# Generated by FakeRAM 2.0
VERSION 5.7 ;
BUSBITCHARS "[]" ;
PROPERTYDEFINITIONS
  MACRO width INTEGER ;
  MACRO depth INTEGER ;
  MACRO banks INTEGER ;
END PROPERTYDEFINITIONS
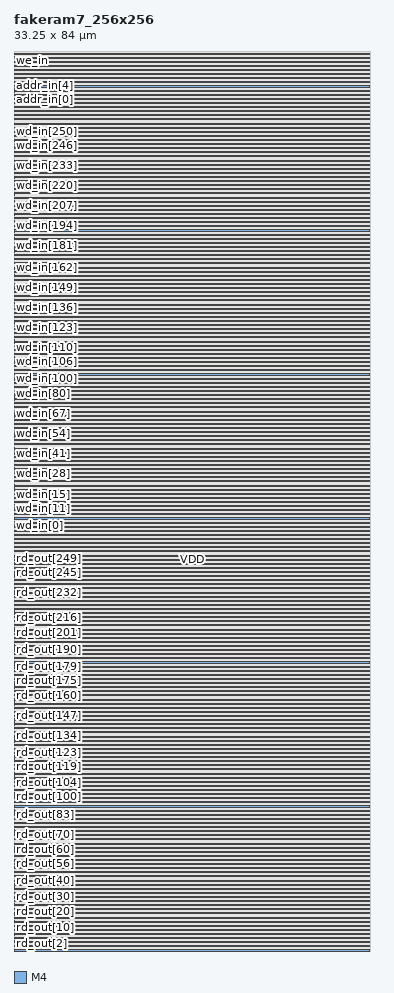
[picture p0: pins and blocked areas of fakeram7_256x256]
MACRO fakeram7_256x256
  PROPERTY width 256 ;
  PROPERTY depth 256 ;
  PROPERTY banks 1 ;
  FOREIGN fakeram7_256x256 0 0 ;
  SYMMETRY X Y R90 ;
  SIZE 33.250 BY 84.000 ;
  CLASS BLOCK ;
  PIN rd_out[0]
    DIRECTION OUTPUT ;
    USE SIGNAL ;
    SHAPE ABUTMENT ;
    PORT
      LAYER M4 ;
      RECT 0.000 0.048 0.024 0.072 ;
    END
  END rd_out[0]
  PIN rd_out[1]
    DIRECTION OUTPUT ;
    USE SIGNAL ;
    SHAPE ABUTMENT ;
    PORT
      LAYER M4 ;
      RECT 0.000 0.192 0.024 0.216 ;
    END
  END rd_out[1]
  PIN rd_out[2]
    DIRECTION OUTPUT ;
    USE SIGNAL ;
    SHAPE ABUTMENT ;
    PORT
      LAYER M4 ;
      RECT 0.000 0.336 0.024 0.360 ;
    END
  END rd_out[2]
  PIN rd_out[3]
    DIRECTION OUTPUT ;
    USE SIGNAL ;
    SHAPE ABUTMENT ;
    PORT
      LAYER M4 ;
      RECT 0.000 0.480 0.024 0.504 ;
    END
  END rd_out[3]
  PIN rd_out[4]
    DIRECTION OUTPUT ;
    USE SIGNAL ;
    SHAPE ABUTMENT ;
    PORT
      LAYER M4 ;
      RECT 0.000 0.624 0.024 0.648 ;
    END
  END rd_out[4]
  PIN rd_out[5]
    DIRECTION OUTPUT ;
    USE SIGNAL ;
    SHAPE ABUTMENT ;
    PORT
      LAYER M4 ;
      RECT 0.000 0.768 0.024 0.792 ;
    END
  END rd_out[5]
  PIN rd_out[6]
    DIRECTION OUTPUT ;
    USE SIGNAL ;
    SHAPE ABUTMENT ;
    PORT
      LAYER M4 ;
      RECT 0.000 0.912 0.024 0.936 ;
    END
  END rd_out[6]
  PIN rd_out[7]
    DIRECTION OUTPUT ;
    USE SIGNAL ;
    SHAPE ABUTMENT ;
    PORT
      LAYER M4 ;
      RECT 0.000 1.056 0.024 1.080 ;
    END
  END rd_out[7]
  PIN rd_out[8]
    DIRECTION OUTPUT ;
    USE SIGNAL ;
    SHAPE ABUTMENT ;
    PORT
      LAYER M4 ;
      RECT 0.000 1.200 0.024 1.224 ;
    END
  END rd_out[8]
  PIN rd_out[9]
    DIRECTION OUTPUT ;
    USE SIGNAL ;
    SHAPE ABUTMENT ;
    PORT
      LAYER M4 ;
      RECT 0.000 1.344 0.024 1.368 ;
    END
  END rd_out[9]
  PIN rd_out[10]
    DIRECTION OUTPUT ;
    USE SIGNAL ;
    SHAPE ABUTMENT ;
    PORT
      LAYER M4 ;
      RECT 0.000 1.488 0.024 1.512 ;
    END
  END rd_out[10]
  PIN rd_out[11]
    DIRECTION OUTPUT ;
    USE SIGNAL ;
    SHAPE ABUTMENT ;
    PORT
      LAYER M4 ;
      RECT 0.000 1.632 0.024 1.656 ;
    END
  END rd_out[11]
  PIN rd_out[12]
    DIRECTION OUTPUT ;
    USE SIGNAL ;
    SHAPE ABUTMENT ;
    PORT
      LAYER M4 ;
      RECT 0.000 1.776 0.024 1.800 ;
    END
  END rd_out[12]
  PIN rd_out[13]
    DIRECTION OUTPUT ;
    USE SIGNAL ;
    SHAPE ABUTMENT ;
    PORT
      LAYER M4 ;
      RECT 0.000 1.920 0.024 1.944 ;
    END
  END rd_out[13]
  PIN rd_out[14]
    DIRECTION OUTPUT ;
    USE SIGNAL ;
    SHAPE ABUTMENT ;
    PORT
      LAYER M4 ;
      RECT 0.000 2.064 0.024 2.088 ;
    END
  END rd_out[14]
  PIN rd_out[15]
    DIRECTION OUTPUT ;
    USE SIGNAL ;
    SHAPE ABUTMENT ;
    PORT
      LAYER M4 ;
      RECT 0.000 2.208 0.024 2.232 ;
    END
  END rd_out[15]
  PIN rd_out[16]
    DIRECTION OUTPUT ;
    USE SIGNAL ;
    SHAPE ABUTMENT ;
    PORT
      LAYER M4 ;
      RECT 0.000 2.352 0.024 2.376 ;
    END
  END rd_out[16]
  PIN rd_out[17]
    DIRECTION OUTPUT ;
    USE SIGNAL ;
    SHAPE ABUTMENT ;
    PORT
      LAYER M4 ;
      RECT 0.000 2.496 0.024 2.520 ;
    END
  END rd_out[17]
  PIN rd_out[18]
    DIRECTION OUTPUT ;
    USE SIGNAL ;
    SHAPE ABUTMENT ;
    PORT
      LAYER M4 ;
      RECT 0.000 2.640 0.024 2.664 ;
    END
  END rd_out[18]
  PIN rd_out[19]
    DIRECTION OUTPUT ;
    USE SIGNAL ;
    SHAPE ABUTMENT ;
    PORT
      LAYER M4 ;
      RECT 0.000 2.784 0.024 2.808 ;
    END
  END rd_out[19]
  PIN rd_out[20]
    DIRECTION OUTPUT ;
    USE SIGNAL ;
    SHAPE ABUTMENT ;
    PORT
      LAYER M4 ;
      RECT 0.000 2.928 0.024 2.952 ;
    END
  END rd_out[20]
  PIN rd_out[21]
    DIRECTION OUTPUT ;
    USE SIGNAL ;
    SHAPE ABUTMENT ;
    PORT
      LAYER M4 ;
      RECT 0.000 3.072 0.024 3.096 ;
    END
  END rd_out[21]
  PIN rd_out[22]
    DIRECTION OUTPUT ;
    USE SIGNAL ;
    SHAPE ABUTMENT ;
    PORT
      LAYER M4 ;
      RECT 0.000 3.216 0.024 3.240 ;
    END
  END rd_out[22]
  PIN rd_out[23]
    DIRECTION OUTPUT ;
    USE SIGNAL ;
    SHAPE ABUTMENT ;
    PORT
      LAYER M4 ;
      RECT 0.000 3.360 0.024 3.384 ;
    END
  END rd_out[23]
  PIN rd_out[24]
    DIRECTION OUTPUT ;
    USE SIGNAL ;
    SHAPE ABUTMENT ;
    PORT
      LAYER M4 ;
      RECT 0.000 3.504 0.024 3.528 ;
    END
  END rd_out[24]
  PIN rd_out[25]
    DIRECTION OUTPUT ;
    USE SIGNAL ;
    SHAPE ABUTMENT ;
    PORT
      LAYER M4 ;
      RECT 0.000 3.648 0.024 3.672 ;
    END
  END rd_out[25]
  PIN rd_out[26]
    DIRECTION OUTPUT ;
    USE SIGNAL ;
    SHAPE ABUTMENT ;
    PORT
      LAYER M4 ;
      RECT 0.000 3.792 0.024 3.816 ;
    END
  END rd_out[26]
  PIN rd_out[27]
    DIRECTION OUTPUT ;
    USE SIGNAL ;
    SHAPE ABUTMENT ;
    PORT
      LAYER M4 ;
      RECT 0.000 3.936 0.024 3.960 ;
    END
  END rd_out[27]
  PIN rd_out[28]
    DIRECTION OUTPUT ;
    USE SIGNAL ;
    SHAPE ABUTMENT ;
    PORT
      LAYER M4 ;
      RECT 0.000 4.080 0.024 4.104 ;
    END
  END rd_out[28]
  PIN rd_out[29]
    DIRECTION OUTPUT ;
    USE SIGNAL ;
    SHAPE ABUTMENT ;
    PORT
      LAYER M4 ;
      RECT 0.000 4.224 0.024 4.248 ;
    END
  END rd_out[29]
  PIN rd_out[30]
    DIRECTION OUTPUT ;
    USE SIGNAL ;
    SHAPE ABUTMENT ;
    PORT
      LAYER M4 ;
      RECT 0.000 4.368 0.024 4.392 ;
    END
  END rd_out[30]
  PIN rd_out[31]
    DIRECTION OUTPUT ;
    USE SIGNAL ;
    SHAPE ABUTMENT ;
    PORT
      LAYER M4 ;
      RECT 0.000 4.512 0.024 4.536 ;
    END
  END rd_out[31]
  PIN rd_out[32]
    DIRECTION OUTPUT ;
    USE SIGNAL ;
    SHAPE ABUTMENT ;
    PORT
      LAYER M4 ;
      RECT 0.000 4.656 0.024 4.680 ;
    END
  END rd_out[32]
  PIN rd_out[33]
    DIRECTION OUTPUT ;
    USE SIGNAL ;
    SHAPE ABUTMENT ;
    PORT
      LAYER M4 ;
      RECT 0.000 4.800 0.024 4.824 ;
    END
  END rd_out[33]
  PIN rd_out[34]
    DIRECTION OUTPUT ;
    USE SIGNAL ;
    SHAPE ABUTMENT ;
    PORT
      LAYER M4 ;
      RECT 0.000 4.944 0.024 4.968 ;
    END
  END rd_out[34]
  PIN rd_out[35]
    DIRECTION OUTPUT ;
    USE SIGNAL ;
    SHAPE ABUTMENT ;
    PORT
      LAYER M4 ;
      RECT 0.000 5.088 0.024 5.112 ;
    END
  END rd_out[35]
  PIN rd_out[36]
    DIRECTION OUTPUT ;
    USE SIGNAL ;
    SHAPE ABUTMENT ;
    PORT
      LAYER M4 ;
      RECT 0.000 5.232 0.024 5.256 ;
    END
  END rd_out[36]
  PIN rd_out[37]
    DIRECTION OUTPUT ;
    USE SIGNAL ;
    SHAPE ABUTMENT ;
    PORT
      LAYER M4 ;
      RECT 0.000 5.376 0.024 5.400 ;
    END
  END rd_out[37]
  PIN rd_out[38]
    DIRECTION OUTPUT ;
    USE SIGNAL ;
    SHAPE ABUTMENT ;
    PORT
      LAYER M4 ;
      RECT 0.000 5.520 0.024 5.544 ;
    END
  END rd_out[38]
  PIN rd_out[39]
    DIRECTION OUTPUT ;
    USE SIGNAL ;
    SHAPE ABUTMENT ;
    PORT
      LAYER M4 ;
      RECT 0.000 5.664 0.024 5.688 ;
    END
  END rd_out[39]
  PIN rd_out[40]
    DIRECTION OUTPUT ;
    USE SIGNAL ;
    SHAPE ABUTMENT ;
    PORT
      LAYER M4 ;
      RECT 0.000 5.808 0.024 5.832 ;
    END
  END rd_out[40]
  PIN rd_out[41]
    DIRECTION OUTPUT ;
    USE SIGNAL ;
    SHAPE ABUTMENT ;
    PORT
      LAYER M4 ;
      RECT 0.000 5.952 0.024 5.976 ;
    END
  END rd_out[41]
  PIN rd_out[42]
    DIRECTION OUTPUT ;
    USE SIGNAL ;
    SHAPE ABUTMENT ;
    PORT
      LAYER M4 ;
      RECT 0.000 6.096 0.024 6.120 ;
    END
  END rd_out[42]
  PIN rd_out[43]
    DIRECTION OUTPUT ;
    USE SIGNAL ;
    SHAPE ABUTMENT ;
    PORT
      LAYER M4 ;
      RECT 0.000 6.240 0.024 6.264 ;
    END
  END rd_out[43]
  PIN rd_out[44]
    DIRECTION OUTPUT ;
    USE SIGNAL ;
    SHAPE ABUTMENT ;
    PORT
      LAYER M4 ;
      RECT 0.000 6.384 0.024 6.408 ;
    END
  END rd_out[44]
  PIN rd_out[45]
    DIRECTION OUTPUT ;
    USE SIGNAL ;
    SHAPE ABUTMENT ;
    PORT
      LAYER M4 ;
      RECT 0.000 6.528 0.024 6.552 ;
    END
  END rd_out[45]
  PIN rd_out[46]
    DIRECTION OUTPUT ;
    USE SIGNAL ;
    SHAPE ABUTMENT ;
    PORT
      LAYER M4 ;
      RECT 0.000 6.672 0.024 6.696 ;
    END
  END rd_out[46]
  PIN rd_out[47]
    DIRECTION OUTPUT ;
    USE SIGNAL ;
    SHAPE ABUTMENT ;
    PORT
      LAYER M4 ;
      RECT 0.000 6.816 0.024 6.840 ;
    END
  END rd_out[47]
  PIN rd_out[48]
    DIRECTION OUTPUT ;
    USE SIGNAL ;
    SHAPE ABUTMENT ;
    PORT
      LAYER M4 ;
      RECT 0.000 6.960 0.024 6.984 ;
    END
  END rd_out[48]
  PIN rd_out[49]
    DIRECTION OUTPUT ;
    USE SIGNAL ;
    SHAPE ABUTMENT ;
    PORT
      LAYER M4 ;
      RECT 0.000 7.104 0.024 7.128 ;
    END
  END rd_out[49]
  PIN rd_out[50]
    DIRECTION OUTPUT ;
    USE SIGNAL ;
    SHAPE ABUTMENT ;
    PORT
      LAYER M4 ;
      RECT 0.000 7.248 0.024 7.272 ;
    END
  END rd_out[50]
  PIN rd_out[51]
    DIRECTION OUTPUT ;
    USE SIGNAL ;
    SHAPE ABUTMENT ;
    PORT
      LAYER M4 ;
      RECT 0.000 7.392 0.024 7.416 ;
    END
  END rd_out[51]
  PIN rd_out[52]
    DIRECTION OUTPUT ;
    USE SIGNAL ;
    SHAPE ABUTMENT ;
    PORT
      LAYER M4 ;
      RECT 0.000 7.536 0.024 7.560 ;
    END
  END rd_out[52]
  PIN rd_out[53]
    DIRECTION OUTPUT ;
    USE SIGNAL ;
    SHAPE ABUTMENT ;
    PORT
      LAYER M4 ;
      RECT 0.000 7.680 0.024 7.704 ;
    END
  END rd_out[53]
  PIN rd_out[54]
    DIRECTION OUTPUT ;
    USE SIGNAL ;
    SHAPE ABUTMENT ;
    PORT
      LAYER M4 ;
      RECT 0.000 7.824 0.024 7.848 ;
    END
  END rd_out[54]
  PIN rd_out[55]
    DIRECTION OUTPUT ;
    USE SIGNAL ;
    SHAPE ABUTMENT ;
    PORT
      LAYER M4 ;
      RECT 0.000 7.968 0.024 7.992 ;
    END
  END rd_out[55]
  PIN rd_out[56]
    DIRECTION OUTPUT ;
    USE SIGNAL ;
    SHAPE ABUTMENT ;
    PORT
      LAYER M4 ;
      RECT 0.000 8.112 0.024 8.136 ;
    END
  END rd_out[56]
  PIN rd_out[57]
    DIRECTION OUTPUT ;
    USE SIGNAL ;
    SHAPE ABUTMENT ;
    PORT
      LAYER M4 ;
      RECT 0.000 8.256 0.024 8.280 ;
    END
  END rd_out[57]
  PIN rd_out[58]
    DIRECTION OUTPUT ;
    USE SIGNAL ;
    SHAPE ABUTMENT ;
    PORT
      LAYER M4 ;
      RECT 0.000 8.400 0.024 8.424 ;
    END
  END rd_out[58]
  PIN rd_out[59]
    DIRECTION OUTPUT ;
    USE SIGNAL ;
    SHAPE ABUTMENT ;
    PORT
      LAYER M4 ;
      RECT 0.000 8.544 0.024 8.568 ;
    END
  END rd_out[59]
  PIN rd_out[60]
    DIRECTION OUTPUT ;
    USE SIGNAL ;
    SHAPE ABUTMENT ;
    PORT
      LAYER M4 ;
      RECT 0.000 8.688 0.024 8.712 ;
    END
  END rd_out[60]
  PIN rd_out[61]
    DIRECTION OUTPUT ;
    USE SIGNAL ;
    SHAPE ABUTMENT ;
    PORT
      LAYER M4 ;
      RECT 0.000 8.832 0.024 8.856 ;
    END
  END rd_out[61]
  PIN rd_out[62]
    DIRECTION OUTPUT ;
    USE SIGNAL ;
    SHAPE ABUTMENT ;
    PORT
      LAYER M4 ;
      RECT 0.000 8.976 0.024 9.000 ;
    END
  END rd_out[62]
  PIN rd_out[63]
    DIRECTION OUTPUT ;
    USE SIGNAL ;
    SHAPE ABUTMENT ;
    PORT
      LAYER M4 ;
      RECT 0.000 9.120 0.024 9.144 ;
    END
  END rd_out[63]
  PIN rd_out[64]
    DIRECTION OUTPUT ;
    USE SIGNAL ;
    SHAPE ABUTMENT ;
    PORT
      LAYER M4 ;
      RECT 0.000 9.264 0.024 9.288 ;
    END
  END rd_out[64]
  PIN rd_out[65]
    DIRECTION OUTPUT ;
    USE SIGNAL ;
    SHAPE ABUTMENT ;
    PORT
      LAYER M4 ;
      RECT 0.000 9.408 0.024 9.432 ;
    END
  END rd_out[65]
  PIN rd_out[66]
    DIRECTION OUTPUT ;
    USE SIGNAL ;
    SHAPE ABUTMENT ;
    PORT
      LAYER M4 ;
      RECT 0.000 9.552 0.024 9.576 ;
    END
  END rd_out[66]
  PIN rd_out[67]
    DIRECTION OUTPUT ;
    USE SIGNAL ;
    SHAPE ABUTMENT ;
    PORT
      LAYER M4 ;
      RECT 0.000 9.696 0.024 9.720 ;
    END
  END rd_out[67]
  PIN rd_out[68]
    DIRECTION OUTPUT ;
    USE SIGNAL ;
    SHAPE ABUTMENT ;
    PORT
      LAYER M4 ;
      RECT 0.000 9.840 0.024 9.864 ;
    END
  END rd_out[68]
  PIN rd_out[69]
    DIRECTION OUTPUT ;
    USE SIGNAL ;
    SHAPE ABUTMENT ;
    PORT
      LAYER M4 ;
      RECT 0.000 9.984 0.024 10.008 ;
    END
  END rd_out[69]
  PIN rd_out[70]
    DIRECTION OUTPUT ;
    USE SIGNAL ;
    SHAPE ABUTMENT ;
    PORT
      LAYER M4 ;
      RECT 0.000 10.128 0.024 10.152 ;
    END
  END rd_out[70]
  PIN rd_out[71]
    DIRECTION OUTPUT ;
    USE SIGNAL ;
    SHAPE ABUTMENT ;
    PORT
      LAYER M4 ;
      RECT 0.000 10.272 0.024 10.296 ;
    END
  END rd_out[71]
  PIN rd_out[72]
    DIRECTION OUTPUT ;
    USE SIGNAL ;
    SHAPE ABUTMENT ;
    PORT
      LAYER M4 ;
      RECT 0.000 10.416 0.024 10.440 ;
    END
  END rd_out[72]
  PIN rd_out[73]
    DIRECTION OUTPUT ;
    USE SIGNAL ;
    SHAPE ABUTMENT ;
    PORT
      LAYER M4 ;
      RECT 0.000 10.560 0.024 10.584 ;
    END
  END rd_out[73]
  PIN rd_out[74]
    DIRECTION OUTPUT ;
    USE SIGNAL ;
    SHAPE ABUTMENT ;
    PORT
      LAYER M4 ;
      RECT 0.000 10.704 0.024 10.728 ;
    END
  END rd_out[74]
  PIN rd_out[75]
    DIRECTION OUTPUT ;
    USE SIGNAL ;
    SHAPE ABUTMENT ;
    PORT
      LAYER M4 ;
      RECT 0.000 10.848 0.024 10.872 ;
    END
  END rd_out[75]
  PIN rd_out[76]
    DIRECTION OUTPUT ;
    USE SIGNAL ;
    SHAPE ABUTMENT ;
    PORT
      LAYER M4 ;
      RECT 0.000 10.992 0.024 11.016 ;
    END
  END rd_out[76]
  PIN rd_out[77]
    DIRECTION OUTPUT ;
    USE SIGNAL ;
    SHAPE ABUTMENT ;
    PORT
      LAYER M4 ;
      RECT 0.000 11.136 0.024 11.160 ;
    END
  END rd_out[77]
  PIN rd_out[78]
    DIRECTION OUTPUT ;
    USE SIGNAL ;
    SHAPE ABUTMENT ;
    PORT
      LAYER M4 ;
      RECT 0.000 11.280 0.024 11.304 ;
    END
  END rd_out[78]
  PIN rd_out[79]
    DIRECTION OUTPUT ;
    USE SIGNAL ;
    SHAPE ABUTMENT ;
    PORT
      LAYER M4 ;
      RECT 0.000 11.424 0.024 11.448 ;
    END
  END rd_out[79]
  PIN rd_out[80]
    DIRECTION OUTPUT ;
    USE SIGNAL ;
    SHAPE ABUTMENT ;
    PORT
      LAYER M4 ;
      RECT 0.000 11.568 0.024 11.592 ;
    END
  END rd_out[80]
  PIN rd_out[81]
    DIRECTION OUTPUT ;
    USE SIGNAL ;
    SHAPE ABUTMENT ;
    PORT
      LAYER M4 ;
      RECT 0.000 11.712 0.024 11.736 ;
    END
  END rd_out[81]
  PIN rd_out[82]
    DIRECTION OUTPUT ;
    USE SIGNAL ;
    SHAPE ABUTMENT ;
    PORT
      LAYER M4 ;
      RECT 0.000 11.856 0.024 11.880 ;
    END
  END rd_out[82]
  PIN rd_out[83]
    DIRECTION OUTPUT ;
    USE SIGNAL ;
    SHAPE ABUTMENT ;
    PORT
      LAYER M4 ;
      RECT 0.000 12.000 0.024 12.024 ;
    END
  END rd_out[83]
  PIN rd_out[84]
    DIRECTION OUTPUT ;
    USE SIGNAL ;
    SHAPE ABUTMENT ;
    PORT
      LAYER M4 ;
      RECT 0.000 12.144 0.024 12.168 ;
    END
  END rd_out[84]
  PIN rd_out[85]
    DIRECTION OUTPUT ;
    USE SIGNAL ;
    SHAPE ABUTMENT ;
    PORT
      LAYER M4 ;
      RECT 0.000 12.288 0.024 12.312 ;
    END
  END rd_out[85]
  PIN rd_out[86]
    DIRECTION OUTPUT ;
    USE SIGNAL ;
    SHAPE ABUTMENT ;
    PORT
      LAYER M4 ;
      RECT 0.000 12.432 0.024 12.456 ;
    END
  END rd_out[86]
  PIN rd_out[87]
    DIRECTION OUTPUT ;
    USE SIGNAL ;
    SHAPE ABUTMENT ;
    PORT
      LAYER M4 ;
      RECT 0.000 12.576 0.024 12.600 ;
    END
  END rd_out[87]
  PIN rd_out[88]
    DIRECTION OUTPUT ;
    USE SIGNAL ;
    SHAPE ABUTMENT ;
    PORT
      LAYER M4 ;
      RECT 0.000 12.720 0.024 12.744 ;
    END
  END rd_out[88]
  PIN rd_out[89]
    DIRECTION OUTPUT ;
    USE SIGNAL ;
    SHAPE ABUTMENT ;
    PORT
      LAYER M4 ;
      RECT 0.000 12.864 0.024 12.888 ;
    END
  END rd_out[89]
  PIN rd_out[90]
    DIRECTION OUTPUT ;
    USE SIGNAL ;
    SHAPE ABUTMENT ;
    PORT
      LAYER M4 ;
      RECT 0.000 13.008 0.024 13.032 ;
    END
  END rd_out[90]
  PIN rd_out[91]
    DIRECTION OUTPUT ;
    USE SIGNAL ;
    SHAPE ABUTMENT ;
    PORT
      LAYER M4 ;
      RECT 0.000 13.152 0.024 13.176 ;
    END
  END rd_out[91]
  PIN rd_out[92]
    DIRECTION OUTPUT ;
    USE SIGNAL ;
    SHAPE ABUTMENT ;
    PORT
      LAYER M4 ;
      RECT 0.000 13.296 0.024 13.320 ;
    END
  END rd_out[92]
  PIN rd_out[93]
    DIRECTION OUTPUT ;
    USE SIGNAL ;
    SHAPE ABUTMENT ;
    PORT
      LAYER M4 ;
      RECT 0.000 13.440 0.024 13.464 ;
    END
  END rd_out[93]
  PIN rd_out[94]
    DIRECTION OUTPUT ;
    USE SIGNAL ;
    SHAPE ABUTMENT ;
    PORT
      LAYER M4 ;
      RECT 0.000 13.584 0.024 13.608 ;
    END
  END rd_out[94]
  PIN rd_out[95]
    DIRECTION OUTPUT ;
    USE SIGNAL ;
    SHAPE ABUTMENT ;
    PORT
      LAYER M4 ;
      RECT 0.000 13.728 0.024 13.752 ;
    END
  END rd_out[95]
  PIN rd_out[96]
    DIRECTION OUTPUT ;
    USE SIGNAL ;
    SHAPE ABUTMENT ;
    PORT
      LAYER M4 ;
      RECT 0.000 13.872 0.024 13.896 ;
    END
  END rd_out[96]
  PIN rd_out[97]
    DIRECTION OUTPUT ;
    USE SIGNAL ;
    SHAPE ABUTMENT ;
    PORT
      LAYER M4 ;
      RECT 0.000 14.016 0.024 14.040 ;
    END
  END rd_out[97]
  PIN rd_out[98]
    DIRECTION OUTPUT ;
    USE SIGNAL ;
    SHAPE ABUTMENT ;
    PORT
      LAYER M4 ;
      RECT 0.000 14.160 0.024 14.184 ;
    END
  END rd_out[98]
  PIN rd_out[99]
    DIRECTION OUTPUT ;
    USE SIGNAL ;
    SHAPE ABUTMENT ;
    PORT
      LAYER M4 ;
      RECT 0.000 14.304 0.024 14.328 ;
    END
  END rd_out[99]
  PIN rd_out[100]
    DIRECTION OUTPUT ;
    USE SIGNAL ;
    SHAPE ABUTMENT ;
    PORT
      LAYER M4 ;
      RECT 0.000 14.448 0.024 14.472 ;
    END
  END rd_out[100]
  PIN rd_out[101]
    DIRECTION OUTPUT ;
    USE SIGNAL ;
    SHAPE ABUTMENT ;
    PORT
      LAYER M4 ;
      RECT 0.000 14.592 0.024 14.616 ;
    END
  END rd_out[101]
  PIN rd_out[102]
    DIRECTION OUTPUT ;
    USE SIGNAL ;
    SHAPE ABUTMENT ;
    PORT
      LAYER M4 ;
      RECT 0.000 14.736 0.024 14.760 ;
    END
  END rd_out[102]
  PIN rd_out[103]
    DIRECTION OUTPUT ;
    USE SIGNAL ;
    SHAPE ABUTMENT ;
    PORT
      LAYER M4 ;
      RECT 0.000 14.880 0.024 14.904 ;
    END
  END rd_out[103]
  PIN rd_out[104]
    DIRECTION OUTPUT ;
    USE SIGNAL ;
    SHAPE ABUTMENT ;
    PORT
      LAYER M4 ;
      RECT 0.000 15.024 0.024 15.048 ;
    END
  END rd_out[104]
  PIN rd_out[105]
    DIRECTION OUTPUT ;
    USE SIGNAL ;
    SHAPE ABUTMENT ;
    PORT
      LAYER M4 ;
      RECT 0.000 15.168 0.024 15.192 ;
    END
  END rd_out[105]
  PIN rd_out[106]
    DIRECTION OUTPUT ;
    USE SIGNAL ;
    SHAPE ABUTMENT ;
    PORT
      LAYER M4 ;
      RECT 0.000 15.312 0.024 15.336 ;
    END
  END rd_out[106]
  PIN rd_out[107]
    DIRECTION OUTPUT ;
    USE SIGNAL ;
    SHAPE ABUTMENT ;
    PORT
      LAYER M4 ;
      RECT 0.000 15.456 0.024 15.480 ;
    END
  END rd_out[107]
  PIN rd_out[108]
    DIRECTION OUTPUT ;
    USE SIGNAL ;
    SHAPE ABUTMENT ;
    PORT
      LAYER M4 ;
      RECT 0.000 15.600 0.024 15.624 ;
    END
  END rd_out[108]
  PIN rd_out[109]
    DIRECTION OUTPUT ;
    USE SIGNAL ;
    SHAPE ABUTMENT ;
    PORT
      LAYER M4 ;
      RECT 0.000 15.744 0.024 15.768 ;
    END
  END rd_out[109]
  PIN rd_out[110]
    DIRECTION OUTPUT ;
    USE SIGNAL ;
    SHAPE ABUTMENT ;
    PORT
      LAYER M4 ;
      RECT 0.000 15.888 0.024 15.912 ;
    END
  END rd_out[110]
  PIN rd_out[111]
    DIRECTION OUTPUT ;
    USE SIGNAL ;
    SHAPE ABUTMENT ;
    PORT
      LAYER M4 ;
      RECT 0.000 16.032 0.024 16.056 ;
    END
  END rd_out[111]
  PIN rd_out[112]
    DIRECTION OUTPUT ;
    USE SIGNAL ;
    SHAPE ABUTMENT ;
    PORT
      LAYER M4 ;
      RECT 0.000 16.176 0.024 16.200 ;
    END
  END rd_out[112]
  PIN rd_out[113]
    DIRECTION OUTPUT ;
    USE SIGNAL ;
    SHAPE ABUTMENT ;
    PORT
      LAYER M4 ;
      RECT 0.000 16.320 0.024 16.344 ;
    END
  END rd_out[113]
  PIN rd_out[114]
    DIRECTION OUTPUT ;
    USE SIGNAL ;
    SHAPE ABUTMENT ;
    PORT
      LAYER M4 ;
      RECT 0.000 16.464 0.024 16.488 ;
    END
  END rd_out[114]
  PIN rd_out[115]
    DIRECTION OUTPUT ;
    USE SIGNAL ;
    SHAPE ABUTMENT ;
    PORT
      LAYER M4 ;
      RECT 0.000 16.608 0.024 16.632 ;
    END
  END rd_out[115]
  PIN rd_out[116]
    DIRECTION OUTPUT ;
    USE SIGNAL ;
    SHAPE ABUTMENT ;
    PORT
      LAYER M4 ;
      RECT 0.000 16.752 0.024 16.776 ;
    END
  END rd_out[116]
  PIN rd_out[117]
    DIRECTION OUTPUT ;
    USE SIGNAL ;
    SHAPE ABUTMENT ;
    PORT
      LAYER M4 ;
      RECT 0.000 16.896 0.024 16.920 ;
    END
  END rd_out[117]
  PIN rd_out[118]
    DIRECTION OUTPUT ;
    USE SIGNAL ;
    SHAPE ABUTMENT ;
    PORT
      LAYER M4 ;
      RECT 0.000 17.040 0.024 17.064 ;
    END
  END rd_out[118]
  PIN rd_out[119]
    DIRECTION OUTPUT ;
    USE SIGNAL ;
    SHAPE ABUTMENT ;
    PORT
      LAYER M4 ;
      RECT 0.000 17.184 0.024 17.208 ;
    END
  END rd_out[119]
  PIN rd_out[120]
    DIRECTION OUTPUT ;
    USE SIGNAL ;
    SHAPE ABUTMENT ;
    PORT
      LAYER M4 ;
      RECT 0.000 17.328 0.024 17.352 ;
    END
  END rd_out[120]
  PIN rd_out[121]
    DIRECTION OUTPUT ;
    USE SIGNAL ;
    SHAPE ABUTMENT ;
    PORT
      LAYER M4 ;
      RECT 0.000 17.472 0.024 17.496 ;
    END
  END rd_out[121]
  PIN rd_out[122]
    DIRECTION OUTPUT ;
    USE SIGNAL ;
    SHAPE ABUTMENT ;
    PORT
      LAYER M4 ;
      RECT 0.000 17.616 0.024 17.640 ;
    END
  END rd_out[122]
  PIN rd_out[123]
    DIRECTION OUTPUT ;
    USE SIGNAL ;
    SHAPE ABUTMENT ;
    PORT
      LAYER M4 ;
      RECT 0.000 17.760 0.024 17.784 ;
    END
  END rd_out[123]
  PIN rd_out[124]
    DIRECTION OUTPUT ;
    USE SIGNAL ;
    SHAPE ABUTMENT ;
    PORT
      LAYER M4 ;
      RECT 0.000 17.904 0.024 17.928 ;
    END
  END rd_out[124]
  PIN rd_out[125]
    DIRECTION OUTPUT ;
    USE SIGNAL ;
    SHAPE ABUTMENT ;
    PORT
      LAYER M4 ;
      RECT 0.000 18.048 0.024 18.072 ;
    END
  END rd_out[125]
  PIN rd_out[126]
    DIRECTION OUTPUT ;
    USE SIGNAL ;
    SHAPE ABUTMENT ;
    PORT
      LAYER M4 ;
      RECT 0.000 18.192 0.024 18.216 ;
    END
  END rd_out[126]
  PIN rd_out[127]
    DIRECTION OUTPUT ;
    USE SIGNAL ;
    SHAPE ABUTMENT ;
    PORT
      LAYER M4 ;
      RECT 0.000 18.336 0.024 18.360 ;
    END
  END rd_out[127]
  PIN rd_out[128]
    DIRECTION OUTPUT ;
    USE SIGNAL ;
    SHAPE ABUTMENT ;
    PORT
      LAYER M4 ;
      RECT 0.000 18.480 0.024 18.504 ;
    END
  END rd_out[128]
  PIN rd_out[129]
    DIRECTION OUTPUT ;
    USE SIGNAL ;
    SHAPE ABUTMENT ;
    PORT
      LAYER M4 ;
      RECT 0.000 18.624 0.024 18.648 ;
    END
  END rd_out[129]
  PIN rd_out[130]
    DIRECTION OUTPUT ;
    USE SIGNAL ;
    SHAPE ABUTMENT ;
    PORT
      LAYER M4 ;
      RECT 0.000 18.768 0.024 18.792 ;
    END
  END rd_out[130]
  PIN rd_out[131]
    DIRECTION OUTPUT ;
    USE SIGNAL ;
    SHAPE ABUTMENT ;
    PORT
      LAYER M4 ;
      RECT 0.000 18.912 0.024 18.936 ;
    END
  END rd_out[131]
  PIN rd_out[132]
    DIRECTION OUTPUT ;
    USE SIGNAL ;
    SHAPE ABUTMENT ;
    PORT
      LAYER M4 ;
      RECT 0.000 19.056 0.024 19.080 ;
    END
  END rd_out[132]
  PIN rd_out[133]
    DIRECTION OUTPUT ;
    USE SIGNAL ;
    SHAPE ABUTMENT ;
    PORT
      LAYER M4 ;
      RECT 0.000 19.200 0.024 19.224 ;
    END
  END rd_out[133]
  PIN rd_out[134]
    DIRECTION OUTPUT ;
    USE SIGNAL ;
    SHAPE ABUTMENT ;
    PORT
      LAYER M4 ;
      RECT 0.000 19.344 0.024 19.368 ;
    END
  END rd_out[134]
  PIN rd_out[135]
    DIRECTION OUTPUT ;
    USE SIGNAL ;
    SHAPE ABUTMENT ;
    PORT
      LAYER M4 ;
      RECT 0.000 19.488 0.024 19.512 ;
    END
  END rd_out[135]
  PIN rd_out[136]
    DIRECTION OUTPUT ;
    USE SIGNAL ;
    SHAPE ABUTMENT ;
    PORT
      LAYER M4 ;
      RECT 0.000 19.632 0.024 19.656 ;
    END
  END rd_out[136]
  PIN rd_out[137]
    DIRECTION OUTPUT ;
    USE SIGNAL ;
    SHAPE ABUTMENT ;
    PORT
      LAYER M4 ;
      RECT 0.000 19.776 0.024 19.800 ;
    END
  END rd_out[137]
  PIN rd_out[138]
    DIRECTION OUTPUT ;
    USE SIGNAL ;
    SHAPE ABUTMENT ;
    PORT
      LAYER M4 ;
      RECT 0.000 19.920 0.024 19.944 ;
    END
  END rd_out[138]
  PIN rd_out[139]
    DIRECTION OUTPUT ;
    USE SIGNAL ;
    SHAPE ABUTMENT ;
    PORT
      LAYER M4 ;
      RECT 0.000 20.064 0.024 20.088 ;
    END
  END rd_out[139]
  PIN rd_out[140]
    DIRECTION OUTPUT ;
    USE SIGNAL ;
    SHAPE ABUTMENT ;
    PORT
      LAYER M4 ;
      RECT 0.000 20.208 0.024 20.232 ;
    END
  END rd_out[140]
  PIN rd_out[141]
    DIRECTION OUTPUT ;
    USE SIGNAL ;
    SHAPE ABUTMENT ;
    PORT
      LAYER M4 ;
      RECT 0.000 20.352 0.024 20.376 ;
    END
  END rd_out[141]
  PIN rd_out[142]
    DIRECTION OUTPUT ;
    USE SIGNAL ;
    SHAPE ABUTMENT ;
    PORT
      LAYER M4 ;
      RECT 0.000 20.496 0.024 20.520 ;
    END
  END rd_out[142]
  PIN rd_out[143]
    DIRECTION OUTPUT ;
    USE SIGNAL ;
    SHAPE ABUTMENT ;
    PORT
      LAYER M4 ;
      RECT 0.000 20.640 0.024 20.664 ;
    END
  END rd_out[143]
  PIN rd_out[144]
    DIRECTION OUTPUT ;
    USE SIGNAL ;
    SHAPE ABUTMENT ;
    PORT
      LAYER M4 ;
      RECT 0.000 20.784 0.024 20.808 ;
    END
  END rd_out[144]
  PIN rd_out[145]
    DIRECTION OUTPUT ;
    USE SIGNAL ;
    SHAPE ABUTMENT ;
    PORT
      LAYER M4 ;
      RECT 0.000 20.928 0.024 20.952 ;
    END
  END rd_out[145]
  PIN rd_out[146]
    DIRECTION OUTPUT ;
    USE SIGNAL ;
    SHAPE ABUTMENT ;
    PORT
      LAYER M4 ;
      RECT 0.000 21.072 0.024 21.096 ;
    END
  END rd_out[146]
  PIN rd_out[147]
    DIRECTION OUTPUT ;
    USE SIGNAL ;
    SHAPE ABUTMENT ;
    PORT
      LAYER M4 ;
      RECT 0.000 21.216 0.024 21.240 ;
    END
  END rd_out[147]
  PIN rd_out[148]
    DIRECTION OUTPUT ;
    USE SIGNAL ;
    SHAPE ABUTMENT ;
    PORT
      LAYER M4 ;
      RECT 0.000 21.360 0.024 21.384 ;
    END
  END rd_out[148]
  PIN rd_out[149]
    DIRECTION OUTPUT ;
    USE SIGNAL ;
    SHAPE ABUTMENT ;
    PORT
      LAYER M4 ;
      RECT 0.000 21.504 0.024 21.528 ;
    END
  END rd_out[149]
  PIN rd_out[150]
    DIRECTION OUTPUT ;
    USE SIGNAL ;
    SHAPE ABUTMENT ;
    PORT
      LAYER M4 ;
      RECT 0.000 21.648 0.024 21.672 ;
    END
  END rd_out[150]
  PIN rd_out[151]
    DIRECTION OUTPUT ;
    USE SIGNAL ;
    SHAPE ABUTMENT ;
    PORT
      LAYER M4 ;
      RECT 0.000 21.792 0.024 21.816 ;
    END
  END rd_out[151]
  PIN rd_out[152]
    DIRECTION OUTPUT ;
    USE SIGNAL ;
    SHAPE ABUTMENT ;
    PORT
      LAYER M4 ;
      RECT 0.000 21.936 0.024 21.960 ;
    END
  END rd_out[152]
  PIN rd_out[153]
    DIRECTION OUTPUT ;
    USE SIGNAL ;
    SHAPE ABUTMENT ;
    PORT
      LAYER M4 ;
      RECT 0.000 22.080 0.024 22.104 ;
    END
  END rd_out[153]
  PIN rd_out[154]
    DIRECTION OUTPUT ;
    USE SIGNAL ;
    SHAPE ABUTMENT ;
    PORT
      LAYER M4 ;
      RECT 0.000 22.224 0.024 22.248 ;
    END
  END rd_out[154]
  PIN rd_out[155]
    DIRECTION OUTPUT ;
    USE SIGNAL ;
    SHAPE ABUTMENT ;
    PORT
      LAYER M4 ;
      RECT 0.000 22.368 0.024 22.392 ;
    END
  END rd_out[155]
  PIN rd_out[156]
    DIRECTION OUTPUT ;
    USE SIGNAL ;
    SHAPE ABUTMENT ;
    PORT
      LAYER M4 ;
      RECT 0.000 22.512 0.024 22.536 ;
    END
  END rd_out[156]
  PIN rd_out[157]
    DIRECTION OUTPUT ;
    USE SIGNAL ;
    SHAPE ABUTMENT ;
    PORT
      LAYER M4 ;
      RECT 0.000 22.656 0.024 22.680 ;
    END
  END rd_out[157]
  PIN rd_out[158]
    DIRECTION OUTPUT ;
    USE SIGNAL ;
    SHAPE ABUTMENT ;
    PORT
      LAYER M4 ;
      RECT 0.000 22.800 0.024 22.824 ;
    END
  END rd_out[158]
  PIN rd_out[159]
    DIRECTION OUTPUT ;
    USE SIGNAL ;
    SHAPE ABUTMENT ;
    PORT
      LAYER M4 ;
      RECT 0.000 22.944 0.024 22.968 ;
    END
  END rd_out[159]
  PIN rd_out[160]
    DIRECTION OUTPUT ;
    USE SIGNAL ;
    SHAPE ABUTMENT ;
    PORT
      LAYER M4 ;
      RECT 0.000 23.088 0.024 23.112 ;
    END
  END rd_out[160]
  PIN rd_out[161]
    DIRECTION OUTPUT ;
    USE SIGNAL ;
    SHAPE ABUTMENT ;
    PORT
      LAYER M4 ;
      RECT 0.000 23.232 0.024 23.256 ;
    END
  END rd_out[161]
  PIN rd_out[162]
    DIRECTION OUTPUT ;
    USE SIGNAL ;
    SHAPE ABUTMENT ;
    PORT
      LAYER M4 ;
      RECT 0.000 23.376 0.024 23.400 ;
    END
  END rd_out[162]
  PIN rd_out[163]
    DIRECTION OUTPUT ;
    USE SIGNAL ;
    SHAPE ABUTMENT ;
    PORT
      LAYER M4 ;
      RECT 0.000 23.520 0.024 23.544 ;
    END
  END rd_out[163]
  PIN rd_out[164]
    DIRECTION OUTPUT ;
    USE SIGNAL ;
    SHAPE ABUTMENT ;
    PORT
      LAYER M4 ;
      RECT 0.000 23.664 0.024 23.688 ;
    END
  END rd_out[164]
  PIN rd_out[165]
    DIRECTION OUTPUT ;
    USE SIGNAL ;
    SHAPE ABUTMENT ;
    PORT
      LAYER M4 ;
      RECT 0.000 23.808 0.024 23.832 ;
    END
  END rd_out[165]
  PIN rd_out[166]
    DIRECTION OUTPUT ;
    USE SIGNAL ;
    SHAPE ABUTMENT ;
    PORT
      LAYER M4 ;
      RECT 0.000 23.952 0.024 23.976 ;
    END
  END rd_out[166]
  PIN rd_out[167]
    DIRECTION OUTPUT ;
    USE SIGNAL ;
    SHAPE ABUTMENT ;
    PORT
      LAYER M4 ;
      RECT 0.000 24.096 0.024 24.120 ;
    END
  END rd_out[167]
  PIN rd_out[168]
    DIRECTION OUTPUT ;
    USE SIGNAL ;
    SHAPE ABUTMENT ;
    PORT
      LAYER M4 ;
      RECT 0.000 24.240 0.024 24.264 ;
    END
  END rd_out[168]
  PIN rd_out[169]
    DIRECTION OUTPUT ;
    USE SIGNAL ;
    SHAPE ABUTMENT ;
    PORT
      LAYER M4 ;
      RECT 0.000 24.384 0.024 24.408 ;
    END
  END rd_out[169]
  PIN rd_out[170]
    DIRECTION OUTPUT ;
    USE SIGNAL ;
    SHAPE ABUTMENT ;
    PORT
      LAYER M4 ;
      RECT 0.000 24.528 0.024 24.552 ;
    END
  END rd_out[170]
  PIN rd_out[171]
    DIRECTION OUTPUT ;
    USE SIGNAL ;
    SHAPE ABUTMENT ;
    PORT
      LAYER M4 ;
      RECT 0.000 24.672 0.024 24.696 ;
    END
  END rd_out[171]
  PIN rd_out[172]
    DIRECTION OUTPUT ;
    USE SIGNAL ;
    SHAPE ABUTMENT ;
    PORT
      LAYER M4 ;
      RECT 0.000 24.816 0.024 24.840 ;
    END
  END rd_out[172]
  PIN rd_out[173]
    DIRECTION OUTPUT ;
    USE SIGNAL ;
    SHAPE ABUTMENT ;
    PORT
      LAYER M4 ;
      RECT 0.000 24.960 0.024 24.984 ;
    END
  END rd_out[173]
  PIN rd_out[174]
    DIRECTION OUTPUT ;
    USE SIGNAL ;
    SHAPE ABUTMENT ;
    PORT
      LAYER M4 ;
      RECT 0.000 25.104 0.024 25.128 ;
    END
  END rd_out[174]
  PIN rd_out[175]
    DIRECTION OUTPUT ;
    USE SIGNAL ;
    SHAPE ABUTMENT ;
    PORT
      LAYER M4 ;
      RECT 0.000 25.248 0.024 25.272 ;
    END
  END rd_out[175]
  PIN rd_out[176]
    DIRECTION OUTPUT ;
    USE SIGNAL ;
    SHAPE ABUTMENT ;
    PORT
      LAYER M4 ;
      RECT 0.000 25.392 0.024 25.416 ;
    END
  END rd_out[176]
  PIN rd_out[177]
    DIRECTION OUTPUT ;
    USE SIGNAL ;
    SHAPE ABUTMENT ;
    PORT
      LAYER M4 ;
      RECT 0.000 25.536 0.024 25.560 ;
    END
  END rd_out[177]
  PIN rd_out[178]
    DIRECTION OUTPUT ;
    USE SIGNAL ;
    SHAPE ABUTMENT ;
    PORT
      LAYER M4 ;
      RECT 0.000 25.680 0.024 25.704 ;
    END
  END rd_out[178]
  PIN rd_out[179]
    DIRECTION OUTPUT ;
    USE SIGNAL ;
    SHAPE ABUTMENT ;
    PORT
      LAYER M4 ;
      RECT 0.000 25.824 0.024 25.848 ;
    END
  END rd_out[179]
  PIN rd_out[180]
    DIRECTION OUTPUT ;
    USE SIGNAL ;
    SHAPE ABUTMENT ;
    PORT
      LAYER M4 ;
      RECT 0.000 25.968 0.024 25.992 ;
    END
  END rd_out[180]
  PIN rd_out[181]
    DIRECTION OUTPUT ;
    USE SIGNAL ;
    SHAPE ABUTMENT ;
    PORT
      LAYER M4 ;
      RECT 0.000 26.112 0.024 26.136 ;
    END
  END rd_out[181]
  PIN rd_out[182]
    DIRECTION OUTPUT ;
    USE SIGNAL ;
    SHAPE ABUTMENT ;
    PORT
      LAYER M4 ;
      RECT 0.000 26.256 0.024 26.280 ;
    END
  END rd_out[182]
  PIN rd_out[183]
    DIRECTION OUTPUT ;
    USE SIGNAL ;
    SHAPE ABUTMENT ;
    PORT
      LAYER M4 ;
      RECT 0.000 26.400 0.024 26.424 ;
    END
  END rd_out[183]
  PIN rd_out[184]
    DIRECTION OUTPUT ;
    USE SIGNAL ;
    SHAPE ABUTMENT ;
    PORT
      LAYER M4 ;
      RECT 0.000 26.544 0.024 26.568 ;
    END
  END rd_out[184]
  PIN rd_out[185]
    DIRECTION OUTPUT ;
    USE SIGNAL ;
    SHAPE ABUTMENT ;
    PORT
      LAYER M4 ;
      RECT 0.000 26.688 0.024 26.712 ;
    END
  END rd_out[185]
  PIN rd_out[186]
    DIRECTION OUTPUT ;
    USE SIGNAL ;
    SHAPE ABUTMENT ;
    PORT
      LAYER M4 ;
      RECT 0.000 26.832 0.024 26.856 ;
    END
  END rd_out[186]
  PIN rd_out[187]
    DIRECTION OUTPUT ;
    USE SIGNAL ;
    SHAPE ABUTMENT ;
    PORT
      LAYER M4 ;
      RECT 0.000 26.976 0.024 27.000 ;
    END
  END rd_out[187]
  PIN rd_out[188]
    DIRECTION OUTPUT ;
    USE SIGNAL ;
    SHAPE ABUTMENT ;
    PORT
      LAYER M4 ;
      RECT 0.000 27.120 0.024 27.144 ;
    END
  END rd_out[188]
  PIN rd_out[189]
    DIRECTION OUTPUT ;
    USE SIGNAL ;
    SHAPE ABUTMENT ;
    PORT
      LAYER M4 ;
      RECT 0.000 27.264 0.024 27.288 ;
    END
  END rd_out[189]
  PIN rd_out[190]
    DIRECTION OUTPUT ;
    USE SIGNAL ;
    SHAPE ABUTMENT ;
    PORT
      LAYER M4 ;
      RECT 0.000 27.408 0.024 27.432 ;
    END
  END rd_out[190]
  PIN rd_out[191]
    DIRECTION OUTPUT ;
    USE SIGNAL ;
    SHAPE ABUTMENT ;
    PORT
      LAYER M4 ;
      RECT 0.000 27.552 0.024 27.576 ;
    END
  END rd_out[191]
  PIN rd_out[192]
    DIRECTION OUTPUT ;
    USE SIGNAL ;
    SHAPE ABUTMENT ;
    PORT
      LAYER M4 ;
      RECT 0.000 27.696 0.024 27.720 ;
    END
  END rd_out[192]
  PIN rd_out[193]
    DIRECTION OUTPUT ;
    USE SIGNAL ;
    SHAPE ABUTMENT ;
    PORT
      LAYER M4 ;
      RECT 0.000 27.840 0.024 27.864 ;
    END
  END rd_out[193]
  PIN rd_out[194]
    DIRECTION OUTPUT ;
    USE SIGNAL ;
    SHAPE ABUTMENT ;
    PORT
      LAYER M4 ;
      RECT 0.000 27.984 0.024 28.008 ;
    END
  END rd_out[194]
  PIN rd_out[195]
    DIRECTION OUTPUT ;
    USE SIGNAL ;
    SHAPE ABUTMENT ;
    PORT
      LAYER M4 ;
      RECT 0.000 28.128 0.024 28.152 ;
    END
  END rd_out[195]
  PIN rd_out[196]
    DIRECTION OUTPUT ;
    USE SIGNAL ;
    SHAPE ABUTMENT ;
    PORT
      LAYER M4 ;
      RECT 0.000 28.272 0.024 28.296 ;
    END
  END rd_out[196]
  PIN rd_out[197]
    DIRECTION OUTPUT ;
    USE SIGNAL ;
    SHAPE ABUTMENT ;
    PORT
      LAYER M4 ;
      RECT 0.000 28.416 0.024 28.440 ;
    END
  END rd_out[197]
  PIN rd_out[198]
    DIRECTION OUTPUT ;
    USE SIGNAL ;
    SHAPE ABUTMENT ;
    PORT
      LAYER M4 ;
      RECT 0.000 28.560 0.024 28.584 ;
    END
  END rd_out[198]
  PIN rd_out[199]
    DIRECTION OUTPUT ;
    USE SIGNAL ;
    SHAPE ABUTMENT ;
    PORT
      LAYER M4 ;
      RECT 0.000 28.704 0.024 28.728 ;
    END
  END rd_out[199]
  PIN rd_out[200]
    DIRECTION OUTPUT ;
    USE SIGNAL ;
    SHAPE ABUTMENT ;
    PORT
      LAYER M4 ;
      RECT 0.000 28.848 0.024 28.872 ;
    END
  END rd_out[200]
  PIN rd_out[201]
    DIRECTION OUTPUT ;
    USE SIGNAL ;
    SHAPE ABUTMENT ;
    PORT
      LAYER M4 ;
      RECT 0.000 28.992 0.024 29.016 ;
    END
  END rd_out[201]
  PIN rd_out[202]
    DIRECTION OUTPUT ;
    USE SIGNAL ;
    SHAPE ABUTMENT ;
    PORT
      LAYER M4 ;
      RECT 0.000 29.136 0.024 29.160 ;
    END
  END rd_out[202]
  PIN rd_out[203]
    DIRECTION OUTPUT ;
    USE SIGNAL ;
    SHAPE ABUTMENT ;
    PORT
      LAYER M4 ;
      RECT 0.000 29.280 0.024 29.304 ;
    END
  END rd_out[203]
  PIN rd_out[204]
    DIRECTION OUTPUT ;
    USE SIGNAL ;
    SHAPE ABUTMENT ;
    PORT
      LAYER M4 ;
      RECT 0.000 29.424 0.024 29.448 ;
    END
  END rd_out[204]
  PIN rd_out[205]
    DIRECTION OUTPUT ;
    USE SIGNAL ;
    SHAPE ABUTMENT ;
    PORT
      LAYER M4 ;
      RECT 0.000 29.568 0.024 29.592 ;
    END
  END rd_out[205]
  PIN rd_out[206]
    DIRECTION OUTPUT ;
    USE SIGNAL ;
    SHAPE ABUTMENT ;
    PORT
      LAYER M4 ;
      RECT 0.000 29.712 0.024 29.736 ;
    END
  END rd_out[206]
  PIN rd_out[207]
    DIRECTION OUTPUT ;
    USE SIGNAL ;
    SHAPE ABUTMENT ;
    PORT
      LAYER M4 ;
      RECT 0.000 29.856 0.024 29.880 ;
    END
  END rd_out[207]
  PIN rd_out[208]
    DIRECTION OUTPUT ;
    USE SIGNAL ;
    SHAPE ABUTMENT ;
    PORT
      LAYER M4 ;
      RECT 0.000 30.000 0.024 30.024 ;
    END
  END rd_out[208]
  PIN rd_out[209]
    DIRECTION OUTPUT ;
    USE SIGNAL ;
    SHAPE ABUTMENT ;
    PORT
      LAYER M4 ;
      RECT 0.000 30.144 0.024 30.168 ;
    END
  END rd_out[209]
  PIN rd_out[210]
    DIRECTION OUTPUT ;
    USE SIGNAL ;
    SHAPE ABUTMENT ;
    PORT
      LAYER M4 ;
      RECT 0.000 30.288 0.024 30.312 ;
    END
  END rd_out[210]
  PIN rd_out[211]
    DIRECTION OUTPUT ;
    USE SIGNAL ;
    SHAPE ABUTMENT ;
    PORT
      LAYER M4 ;
      RECT 0.000 30.432 0.024 30.456 ;
    END
  END rd_out[211]
  PIN rd_out[212]
    DIRECTION OUTPUT ;
    USE SIGNAL ;
    SHAPE ABUTMENT ;
    PORT
      LAYER M4 ;
      RECT 0.000 30.576 0.024 30.600 ;
    END
  END rd_out[212]
  PIN rd_out[213]
    DIRECTION OUTPUT ;
    USE SIGNAL ;
    SHAPE ABUTMENT ;
    PORT
      LAYER M4 ;
      RECT 0.000 30.720 0.024 30.744 ;
    END
  END rd_out[213]
  PIN rd_out[214]
    DIRECTION OUTPUT ;
    USE SIGNAL ;
    SHAPE ABUTMENT ;
    PORT
      LAYER M4 ;
      RECT 0.000 30.864 0.024 30.888 ;
    END
  END rd_out[214]
  PIN rd_out[215]
    DIRECTION OUTPUT ;
    USE SIGNAL ;
    SHAPE ABUTMENT ;
    PORT
      LAYER M4 ;
      RECT 0.000 31.008 0.024 31.032 ;
    END
  END rd_out[215]
  PIN rd_out[216]
    DIRECTION OUTPUT ;
    USE SIGNAL ;
    SHAPE ABUTMENT ;
    PORT
      LAYER M4 ;
      RECT 0.000 31.152 0.024 31.176 ;
    END
  END rd_out[216]
  PIN rd_out[217]
    DIRECTION OUTPUT ;
    USE SIGNAL ;
    SHAPE ABUTMENT ;
    PORT
      LAYER M4 ;
      RECT 0.000 31.296 0.024 31.320 ;
    END
  END rd_out[217]
  PIN rd_out[218]
    DIRECTION OUTPUT ;
    USE SIGNAL ;
    SHAPE ABUTMENT ;
    PORT
      LAYER M4 ;
      RECT 0.000 31.440 0.024 31.464 ;
    END
  END rd_out[218]
  PIN rd_out[219]
    DIRECTION OUTPUT ;
    USE SIGNAL ;
    SHAPE ABUTMENT ;
    PORT
      LAYER M4 ;
      RECT 0.000 31.584 0.024 31.608 ;
    END
  END rd_out[219]
  PIN rd_out[220]
    DIRECTION OUTPUT ;
    USE SIGNAL ;
    SHAPE ABUTMENT ;
    PORT
      LAYER M4 ;
      RECT 0.000 31.728 0.024 31.752 ;
    END
  END rd_out[220]
  PIN rd_out[221]
    DIRECTION OUTPUT ;
    USE SIGNAL ;
    SHAPE ABUTMENT ;
    PORT
      LAYER M4 ;
      RECT 0.000 31.872 0.024 31.896 ;
    END
  END rd_out[221]
  PIN rd_out[222]
    DIRECTION OUTPUT ;
    USE SIGNAL ;
    SHAPE ABUTMENT ;
    PORT
      LAYER M4 ;
      RECT 0.000 32.016 0.024 32.040 ;
    END
  END rd_out[222]
  PIN rd_out[223]
    DIRECTION OUTPUT ;
    USE SIGNAL ;
    SHAPE ABUTMENT ;
    PORT
      LAYER M4 ;
      RECT 0.000 32.160 0.024 32.184 ;
    END
  END rd_out[223]
  PIN rd_out[224]
    DIRECTION OUTPUT ;
    USE SIGNAL ;
    SHAPE ABUTMENT ;
    PORT
      LAYER M4 ;
      RECT 0.000 32.304 0.024 32.328 ;
    END
  END rd_out[224]
  PIN rd_out[225]
    DIRECTION OUTPUT ;
    USE SIGNAL ;
    SHAPE ABUTMENT ;
    PORT
      LAYER M4 ;
      RECT 0.000 32.448 0.024 32.472 ;
    END
  END rd_out[225]
  PIN rd_out[226]
    DIRECTION OUTPUT ;
    USE SIGNAL ;
    SHAPE ABUTMENT ;
    PORT
      LAYER M4 ;
      RECT 0.000 32.592 0.024 32.616 ;
    END
  END rd_out[226]
  PIN rd_out[227]
    DIRECTION OUTPUT ;
    USE SIGNAL ;
    SHAPE ABUTMENT ;
    PORT
      LAYER M4 ;
      RECT 0.000 32.736 0.024 32.760 ;
    END
  END rd_out[227]
  PIN rd_out[228]
    DIRECTION OUTPUT ;
    USE SIGNAL ;
    SHAPE ABUTMENT ;
    PORT
      LAYER M4 ;
      RECT 0.000 32.880 0.024 32.904 ;
    END
  END rd_out[228]
  PIN rd_out[229]
    DIRECTION OUTPUT ;
    USE SIGNAL ;
    SHAPE ABUTMENT ;
    PORT
      LAYER M4 ;
      RECT 0.000 33.024 0.024 33.048 ;
    END
  END rd_out[229]
  PIN rd_out[230]
    DIRECTION OUTPUT ;
    USE SIGNAL ;
    SHAPE ABUTMENT ;
    PORT
      LAYER M4 ;
      RECT 0.000 33.168 0.024 33.192 ;
    END
  END rd_out[230]
  PIN rd_out[231]
    DIRECTION OUTPUT ;
    USE SIGNAL ;
    SHAPE ABUTMENT ;
    PORT
      LAYER M4 ;
      RECT 0.000 33.312 0.024 33.336 ;
    END
  END rd_out[231]
  PIN rd_out[232]
    DIRECTION OUTPUT ;
    USE SIGNAL ;
    SHAPE ABUTMENT ;
    PORT
      LAYER M4 ;
      RECT 0.000 33.456 0.024 33.480 ;
    END
  END rd_out[232]
  PIN rd_out[233]
    DIRECTION OUTPUT ;
    USE SIGNAL ;
    SHAPE ABUTMENT ;
    PORT
      LAYER M4 ;
      RECT 0.000 33.600 0.024 33.624 ;
    END
  END rd_out[233]
  PIN rd_out[234]
    DIRECTION OUTPUT ;
    USE SIGNAL ;
    SHAPE ABUTMENT ;
    PORT
      LAYER M4 ;
      RECT 0.000 33.744 0.024 33.768 ;
    END
  END rd_out[234]
  PIN rd_out[235]
    DIRECTION OUTPUT ;
    USE SIGNAL ;
    SHAPE ABUTMENT ;
    PORT
      LAYER M4 ;
      RECT 0.000 33.888 0.024 33.912 ;
    END
  END rd_out[235]
  PIN rd_out[236]
    DIRECTION OUTPUT ;
    USE SIGNAL ;
    SHAPE ABUTMENT ;
    PORT
      LAYER M4 ;
      RECT 0.000 34.032 0.024 34.056 ;
    END
  END rd_out[236]
  PIN rd_out[237]
    DIRECTION OUTPUT ;
    USE SIGNAL ;
    SHAPE ABUTMENT ;
    PORT
      LAYER M4 ;
      RECT 0.000 34.176 0.024 34.200 ;
    END
  END rd_out[237]
  PIN rd_out[238]
    DIRECTION OUTPUT ;
    USE SIGNAL ;
    SHAPE ABUTMENT ;
    PORT
      LAYER M4 ;
      RECT 0.000 34.320 0.024 34.344 ;
    END
  END rd_out[238]
  PIN rd_out[239]
    DIRECTION OUTPUT ;
    USE SIGNAL ;
    SHAPE ABUTMENT ;
    PORT
      LAYER M4 ;
      RECT 0.000 34.464 0.024 34.488 ;
    END
  END rd_out[239]
  PIN rd_out[240]
    DIRECTION OUTPUT ;
    USE SIGNAL ;
    SHAPE ABUTMENT ;
    PORT
      LAYER M4 ;
      RECT 0.000 34.608 0.024 34.632 ;
    END
  END rd_out[240]
  PIN rd_out[241]
    DIRECTION OUTPUT ;
    USE SIGNAL ;
    SHAPE ABUTMENT ;
    PORT
      LAYER M4 ;
      RECT 0.000 34.752 0.024 34.776 ;
    END
  END rd_out[241]
  PIN rd_out[242]
    DIRECTION OUTPUT ;
    USE SIGNAL ;
    SHAPE ABUTMENT ;
    PORT
      LAYER M4 ;
      RECT 0.000 34.896 0.024 34.920 ;
    END
  END rd_out[242]
  PIN rd_out[243]
    DIRECTION OUTPUT ;
    USE SIGNAL ;
    SHAPE ABUTMENT ;
    PORT
      LAYER M4 ;
      RECT 0.000 35.040 0.024 35.064 ;
    END
  END rd_out[243]
  PIN rd_out[244]
    DIRECTION OUTPUT ;
    USE SIGNAL ;
    SHAPE ABUTMENT ;
    PORT
      LAYER M4 ;
      RECT 0.000 35.184 0.024 35.208 ;
    END
  END rd_out[244]
  PIN rd_out[245]
    DIRECTION OUTPUT ;
    USE SIGNAL ;
    SHAPE ABUTMENT ;
    PORT
      LAYER M4 ;
      RECT 0.000 35.328 0.024 35.352 ;
    END
  END rd_out[245]
  PIN rd_out[246]
    DIRECTION OUTPUT ;
    USE SIGNAL ;
    SHAPE ABUTMENT ;
    PORT
      LAYER M4 ;
      RECT 0.000 35.472 0.024 35.496 ;
    END
  END rd_out[246]
  PIN rd_out[247]
    DIRECTION OUTPUT ;
    USE SIGNAL ;
    SHAPE ABUTMENT ;
    PORT
      LAYER M4 ;
      RECT 0.000 35.616 0.024 35.640 ;
    END
  END rd_out[247]
  PIN rd_out[248]
    DIRECTION OUTPUT ;
    USE SIGNAL ;
    SHAPE ABUTMENT ;
    PORT
      LAYER M4 ;
      RECT 0.000 35.760 0.024 35.784 ;
    END
  END rd_out[248]
  PIN rd_out[249]
    DIRECTION OUTPUT ;
    USE SIGNAL ;
    SHAPE ABUTMENT ;
    PORT
      LAYER M4 ;
      RECT 0.000 35.904 0.024 35.928 ;
    END
  END rd_out[249]
  PIN rd_out[250]
    DIRECTION OUTPUT ;
    USE SIGNAL ;
    SHAPE ABUTMENT ;
    PORT
      LAYER M4 ;
      RECT 0.000 36.048 0.024 36.072 ;
    END
  END rd_out[250]
  PIN rd_out[251]
    DIRECTION OUTPUT ;
    USE SIGNAL ;
    SHAPE ABUTMENT ;
    PORT
      LAYER M4 ;
      RECT 0.000 36.192 0.024 36.216 ;
    END
  END rd_out[251]
  PIN rd_out[252]
    DIRECTION OUTPUT ;
    USE SIGNAL ;
    SHAPE ABUTMENT ;
    PORT
      LAYER M4 ;
      RECT 0.000 36.336 0.024 36.360 ;
    END
  END rd_out[252]
  PIN rd_out[253]
    DIRECTION OUTPUT ;
    USE SIGNAL ;
    SHAPE ABUTMENT ;
    PORT
      LAYER M4 ;
      RECT 0.000 36.480 0.024 36.504 ;
    END
  END rd_out[253]
  PIN rd_out[254]
    DIRECTION OUTPUT ;
    USE SIGNAL ;
    SHAPE ABUTMENT ;
    PORT
      LAYER M4 ;
      RECT 0.000 36.624 0.024 36.648 ;
    END
  END rd_out[254]
  PIN rd_out[255]
    DIRECTION OUTPUT ;
    USE SIGNAL ;
    SHAPE ABUTMENT ;
    PORT
      LAYER M4 ;
      RECT 0.000 36.768 0.024 36.792 ;
    END
  END rd_out[255]
  PIN wd_in[0]
    DIRECTION INPUT ;
    USE SIGNAL ;
    SHAPE ABUTMENT ;
    PORT
      LAYER M4 ;
      RECT 0.000 39.744 0.024 39.768 ;
    END
  END wd_in[0]
  PIN wd_in[1]
    DIRECTION INPUT ;
    USE SIGNAL ;
    SHAPE ABUTMENT ;
    PORT
      LAYER M4 ;
      RECT 0.000 39.888 0.024 39.912 ;
    END
  END wd_in[1]
  PIN wd_in[2]
    DIRECTION INPUT ;
    USE SIGNAL ;
    SHAPE ABUTMENT ;
    PORT
      LAYER M4 ;
      RECT 0.000 40.032 0.024 40.056 ;
    END
  END wd_in[2]
  PIN wd_in[3]
    DIRECTION INPUT ;
    USE SIGNAL ;
    SHAPE ABUTMENT ;
    PORT
      LAYER M4 ;
      RECT 0.000 40.176 0.024 40.200 ;
    END
  END wd_in[3]
  PIN wd_in[4]
    DIRECTION INPUT ;
    USE SIGNAL ;
    SHAPE ABUTMENT ;
    PORT
      LAYER M4 ;
      RECT 0.000 40.320 0.024 40.344 ;
    END
  END wd_in[4]
  PIN wd_in[5]
    DIRECTION INPUT ;
    USE SIGNAL ;
    SHAPE ABUTMENT ;
    PORT
      LAYER M4 ;
      RECT 0.000 40.464 0.024 40.488 ;
    END
  END wd_in[5]
  PIN wd_in[6]
    DIRECTION INPUT ;
    USE SIGNAL ;
    SHAPE ABUTMENT ;
    PORT
      LAYER M4 ;
      RECT 0.000 40.608 0.024 40.632 ;
    END
  END wd_in[6]
  PIN wd_in[7]
    DIRECTION INPUT ;
    USE SIGNAL ;
    SHAPE ABUTMENT ;
    PORT
      LAYER M4 ;
      RECT 0.000 40.752 0.024 40.776 ;
    END
  END wd_in[7]
  PIN wd_in[8]
    DIRECTION INPUT ;
    USE SIGNAL ;
    SHAPE ABUTMENT ;
    PORT
      LAYER M4 ;
      RECT 0.000 40.896 0.024 40.920 ;
    END
  END wd_in[8]
  PIN wd_in[9]
    DIRECTION INPUT ;
    USE SIGNAL ;
    SHAPE ABUTMENT ;
    PORT
      LAYER M4 ;
      RECT 0.000 41.040 0.024 41.064 ;
    END
  END wd_in[9]
  PIN wd_in[10]
    DIRECTION INPUT ;
    USE SIGNAL ;
    SHAPE ABUTMENT ;
    PORT
      LAYER M4 ;
      RECT 0.000 41.184 0.024 41.208 ;
    END
  END wd_in[10]
  PIN wd_in[11]
    DIRECTION INPUT ;
    USE SIGNAL ;
    SHAPE ABUTMENT ;
    PORT
      LAYER M4 ;
      RECT 0.000 41.328 0.024 41.352 ;
    END
  END wd_in[11]
  PIN wd_in[12]
    DIRECTION INPUT ;
    USE SIGNAL ;
    SHAPE ABUTMENT ;
    PORT
      LAYER M4 ;
      RECT 0.000 41.472 0.024 41.496 ;
    END
  END wd_in[12]
  PIN wd_in[13]
    DIRECTION INPUT ;
    USE SIGNAL ;
    SHAPE ABUTMENT ;
    PORT
      LAYER M4 ;
      RECT 0.000 41.616 0.024 41.640 ;
    END
  END wd_in[13]
  PIN wd_in[14]
    DIRECTION INPUT ;
    USE SIGNAL ;
    SHAPE ABUTMENT ;
    PORT
      LAYER M4 ;
      RECT 0.000 41.760 0.024 41.784 ;
    END
  END wd_in[14]
  PIN wd_in[15]
    DIRECTION INPUT ;
    USE SIGNAL ;
    SHAPE ABUTMENT ;
    PORT
      LAYER M4 ;
      RECT 0.000 41.904 0.024 41.928 ;
    END
  END wd_in[15]
  PIN wd_in[16]
    DIRECTION INPUT ;
    USE SIGNAL ;
    SHAPE ABUTMENT ;
    PORT
      LAYER M4 ;
      RECT 0.000 42.048 0.024 42.072 ;
    END
  END wd_in[16]
  PIN wd_in[17]
    DIRECTION INPUT ;
    USE SIGNAL ;
    SHAPE ABUTMENT ;
    PORT
      LAYER M4 ;
      RECT 0.000 42.192 0.024 42.216 ;
    END
  END wd_in[17]
  PIN wd_in[18]
    DIRECTION INPUT ;
    USE SIGNAL ;
    SHAPE ABUTMENT ;
    PORT
      LAYER M4 ;
      RECT 0.000 42.336 0.024 42.360 ;
    END
  END wd_in[18]
  PIN wd_in[19]
    DIRECTION INPUT ;
    USE SIGNAL ;
    SHAPE ABUTMENT ;
    PORT
      LAYER M4 ;
      RECT 0.000 42.480 0.024 42.504 ;
    END
  END wd_in[19]
  PIN wd_in[20]
    DIRECTION INPUT ;
    USE SIGNAL ;
    SHAPE ABUTMENT ;
    PORT
      LAYER M4 ;
      RECT 0.000 42.624 0.024 42.648 ;
    END
  END wd_in[20]
  PIN wd_in[21]
    DIRECTION INPUT ;
    USE SIGNAL ;
    SHAPE ABUTMENT ;
    PORT
      LAYER M4 ;
      RECT 0.000 42.768 0.024 42.792 ;
    END
  END wd_in[21]
  PIN wd_in[22]
    DIRECTION INPUT ;
    USE SIGNAL ;
    SHAPE ABUTMENT ;
    PORT
      LAYER M4 ;
      RECT 0.000 42.912 0.024 42.936 ;
    END
  END wd_in[22]
  PIN wd_in[23]
    DIRECTION INPUT ;
    USE SIGNAL ;
    SHAPE ABUTMENT ;
    PORT
      LAYER M4 ;
      RECT 0.000 43.056 0.024 43.080 ;
    END
  END wd_in[23]
  PIN wd_in[24]
    DIRECTION INPUT ;
    USE SIGNAL ;
    SHAPE ABUTMENT ;
    PORT
      LAYER M4 ;
      RECT 0.000 43.200 0.024 43.224 ;
    END
  END wd_in[24]
  PIN wd_in[25]
    DIRECTION INPUT ;
    USE SIGNAL ;
    SHAPE ABUTMENT ;
    PORT
      LAYER M4 ;
      RECT 0.000 43.344 0.024 43.368 ;
    END
  END wd_in[25]
  PIN wd_in[26]
    DIRECTION INPUT ;
    USE SIGNAL ;
    SHAPE ABUTMENT ;
    PORT
      LAYER M4 ;
      RECT 0.000 43.488 0.024 43.512 ;
    END
  END wd_in[26]
  PIN wd_in[27]
    DIRECTION INPUT ;
    USE SIGNAL ;
    SHAPE ABUTMENT ;
    PORT
      LAYER M4 ;
      RECT 0.000 43.632 0.024 43.656 ;
    END
  END wd_in[27]
  PIN wd_in[28]
    DIRECTION INPUT ;
    USE SIGNAL ;
    SHAPE ABUTMENT ;
    PORT
      LAYER M4 ;
      RECT 0.000 43.776 0.024 43.800 ;
    END
  END wd_in[28]
  PIN wd_in[29]
    DIRECTION INPUT ;
    USE SIGNAL ;
    SHAPE ABUTMENT ;
    PORT
      LAYER M4 ;
      RECT 0.000 43.920 0.024 43.944 ;
    END
  END wd_in[29]
  PIN wd_in[30]
    DIRECTION INPUT ;
    USE SIGNAL ;
    SHAPE ABUTMENT ;
    PORT
      LAYER M4 ;
      RECT 0.000 44.064 0.024 44.088 ;
    END
  END wd_in[30]
  PIN wd_in[31]
    DIRECTION INPUT ;
    USE SIGNAL ;
    SHAPE ABUTMENT ;
    PORT
      LAYER M4 ;
      RECT 0.000 44.208 0.024 44.232 ;
    END
  END wd_in[31]
  PIN wd_in[32]
    DIRECTION INPUT ;
    USE SIGNAL ;
    SHAPE ABUTMENT ;
    PORT
      LAYER M4 ;
      RECT 0.000 44.352 0.024 44.376 ;
    END
  END wd_in[32]
  PIN wd_in[33]
    DIRECTION INPUT ;
    USE SIGNAL ;
    SHAPE ABUTMENT ;
    PORT
      LAYER M4 ;
      RECT 0.000 44.496 0.024 44.520 ;
    END
  END wd_in[33]
  PIN wd_in[34]
    DIRECTION INPUT ;
    USE SIGNAL ;
    SHAPE ABUTMENT ;
    PORT
      LAYER M4 ;
      RECT 0.000 44.640 0.024 44.664 ;
    END
  END wd_in[34]
  PIN wd_in[35]
    DIRECTION INPUT ;
    USE SIGNAL ;
    SHAPE ABUTMENT ;
    PORT
      LAYER M4 ;
      RECT 0.000 44.784 0.024 44.808 ;
    END
  END wd_in[35]
  PIN wd_in[36]
    DIRECTION INPUT ;
    USE SIGNAL ;
    SHAPE ABUTMENT ;
    PORT
      LAYER M4 ;
      RECT 0.000 44.928 0.024 44.952 ;
    END
  END wd_in[36]
  PIN wd_in[37]
    DIRECTION INPUT ;
    USE SIGNAL ;
    SHAPE ABUTMENT ;
    PORT
      LAYER M4 ;
      RECT 0.000 45.072 0.024 45.096 ;
    END
  END wd_in[37]
  PIN wd_in[38]
    DIRECTION INPUT ;
    USE SIGNAL ;
    SHAPE ABUTMENT ;
    PORT
      LAYER M4 ;
      RECT 0.000 45.216 0.024 45.240 ;
    END
  END wd_in[38]
  PIN wd_in[39]
    DIRECTION INPUT ;
    USE SIGNAL ;
    SHAPE ABUTMENT ;
    PORT
      LAYER M4 ;
      RECT 0.000 45.360 0.024 45.384 ;
    END
  END wd_in[39]
  PIN wd_in[40]
    DIRECTION INPUT ;
    USE SIGNAL ;
    SHAPE ABUTMENT ;
    PORT
      LAYER M4 ;
      RECT 0.000 45.504 0.024 45.528 ;
    END
  END wd_in[40]
  PIN wd_in[41]
    DIRECTION INPUT ;
    USE SIGNAL ;
    SHAPE ABUTMENT ;
    PORT
      LAYER M4 ;
      RECT 0.000 45.648 0.024 45.672 ;
    END
  END wd_in[41]
  PIN wd_in[42]
    DIRECTION INPUT ;
    USE SIGNAL ;
    SHAPE ABUTMENT ;
    PORT
      LAYER M4 ;
      RECT 0.000 45.792 0.024 45.816 ;
    END
  END wd_in[42]
  PIN wd_in[43]
    DIRECTION INPUT ;
    USE SIGNAL ;
    SHAPE ABUTMENT ;
    PORT
      LAYER M4 ;
      RECT 0.000 45.936 0.024 45.960 ;
    END
  END wd_in[43]
  PIN wd_in[44]
    DIRECTION INPUT ;
    USE SIGNAL ;
    SHAPE ABUTMENT ;
    PORT
      LAYER M4 ;
      RECT 0.000 46.080 0.024 46.104 ;
    END
  END wd_in[44]
  PIN wd_in[45]
    DIRECTION INPUT ;
    USE SIGNAL ;
    SHAPE ABUTMENT ;
    PORT
      LAYER M4 ;
      RECT 0.000 46.224 0.024 46.248 ;
    END
  END wd_in[45]
  PIN wd_in[46]
    DIRECTION INPUT ;
    USE SIGNAL ;
    SHAPE ABUTMENT ;
    PORT
      LAYER M4 ;
      RECT 0.000 46.368 0.024 46.392 ;
    END
  END wd_in[46]
  PIN wd_in[47]
    DIRECTION INPUT ;
    USE SIGNAL ;
    SHAPE ABUTMENT ;
    PORT
      LAYER M4 ;
      RECT 0.000 46.512 0.024 46.536 ;
    END
  END wd_in[47]
  PIN wd_in[48]
    DIRECTION INPUT ;
    USE SIGNAL ;
    SHAPE ABUTMENT ;
    PORT
      LAYER M4 ;
      RECT 0.000 46.656 0.024 46.680 ;
    END
  END wd_in[48]
  PIN wd_in[49]
    DIRECTION INPUT ;
    USE SIGNAL ;
    SHAPE ABUTMENT ;
    PORT
      LAYER M4 ;
      RECT 0.000 46.800 0.024 46.824 ;
    END
  END wd_in[49]
  PIN wd_in[50]
    DIRECTION INPUT ;
    USE SIGNAL ;
    SHAPE ABUTMENT ;
    PORT
      LAYER M4 ;
      RECT 0.000 46.944 0.024 46.968 ;
    END
  END wd_in[50]
  PIN wd_in[51]
    DIRECTION INPUT ;
    USE SIGNAL ;
    SHAPE ABUTMENT ;
    PORT
      LAYER M4 ;
      RECT 0.000 47.088 0.024 47.112 ;
    END
  END wd_in[51]
  PIN wd_in[52]
    DIRECTION INPUT ;
    USE SIGNAL ;
    SHAPE ABUTMENT ;
    PORT
      LAYER M4 ;
      RECT 0.000 47.232 0.024 47.256 ;
    END
  END wd_in[52]
  PIN wd_in[53]
    DIRECTION INPUT ;
    USE SIGNAL ;
    SHAPE ABUTMENT ;
    PORT
      LAYER M4 ;
      RECT 0.000 47.376 0.024 47.400 ;
    END
  END wd_in[53]
  PIN wd_in[54]
    DIRECTION INPUT ;
    USE SIGNAL ;
    SHAPE ABUTMENT ;
    PORT
      LAYER M4 ;
      RECT 0.000 47.520 0.024 47.544 ;
    END
  END wd_in[54]
  PIN wd_in[55]
    DIRECTION INPUT ;
    USE SIGNAL ;
    SHAPE ABUTMENT ;
    PORT
      LAYER M4 ;
      RECT 0.000 47.664 0.024 47.688 ;
    END
  END wd_in[55]
  PIN wd_in[56]
    DIRECTION INPUT ;
    USE SIGNAL ;
    SHAPE ABUTMENT ;
    PORT
      LAYER M4 ;
      RECT 0.000 47.808 0.024 47.832 ;
    END
  END wd_in[56]
  PIN wd_in[57]
    DIRECTION INPUT ;
    USE SIGNAL ;
    SHAPE ABUTMENT ;
    PORT
      LAYER M4 ;
      RECT 0.000 47.952 0.024 47.976 ;
    END
  END wd_in[57]
  PIN wd_in[58]
    DIRECTION INPUT ;
    USE SIGNAL ;
    SHAPE ABUTMENT ;
    PORT
      LAYER M4 ;
      RECT 0.000 48.096 0.024 48.120 ;
    END
  END wd_in[58]
  PIN wd_in[59]
    DIRECTION INPUT ;
    USE SIGNAL ;
    SHAPE ABUTMENT ;
    PORT
      LAYER M4 ;
      RECT 0.000 48.240 0.024 48.264 ;
    END
  END wd_in[59]
  PIN wd_in[60]
    DIRECTION INPUT ;
    USE SIGNAL ;
    SHAPE ABUTMENT ;
    PORT
      LAYER M4 ;
      RECT 0.000 48.384 0.024 48.408 ;
    END
  END wd_in[60]
  PIN wd_in[61]
    DIRECTION INPUT ;
    USE SIGNAL ;
    SHAPE ABUTMENT ;
    PORT
      LAYER M4 ;
      RECT 0.000 48.528 0.024 48.552 ;
    END
  END wd_in[61]
  PIN wd_in[62]
    DIRECTION INPUT ;
    USE SIGNAL ;
    SHAPE ABUTMENT ;
    PORT
      LAYER M4 ;
      RECT 0.000 48.672 0.024 48.696 ;
    END
  END wd_in[62]
  PIN wd_in[63]
    DIRECTION INPUT ;
    USE SIGNAL ;
    SHAPE ABUTMENT ;
    PORT
      LAYER M4 ;
      RECT 0.000 48.816 0.024 48.840 ;
    END
  END wd_in[63]
  PIN wd_in[64]
    DIRECTION INPUT ;
    USE SIGNAL ;
    SHAPE ABUTMENT ;
    PORT
      LAYER M4 ;
      RECT 0.000 48.960 0.024 48.984 ;
    END
  END wd_in[64]
  PIN wd_in[65]
    DIRECTION INPUT ;
    USE SIGNAL ;
    SHAPE ABUTMENT ;
    PORT
      LAYER M4 ;
      RECT 0.000 49.104 0.024 49.128 ;
    END
  END wd_in[65]
  PIN wd_in[66]
    DIRECTION INPUT ;
    USE SIGNAL ;
    SHAPE ABUTMENT ;
    PORT
      LAYER M4 ;
      RECT 0.000 49.248 0.024 49.272 ;
    END
  END wd_in[66]
  PIN wd_in[67]
    DIRECTION INPUT ;
    USE SIGNAL ;
    SHAPE ABUTMENT ;
    PORT
      LAYER M4 ;
      RECT 0.000 49.392 0.024 49.416 ;
    END
  END wd_in[67]
  PIN wd_in[68]
    DIRECTION INPUT ;
    USE SIGNAL ;
    SHAPE ABUTMENT ;
    PORT
      LAYER M4 ;
      RECT 0.000 49.536 0.024 49.560 ;
    END
  END wd_in[68]
  PIN wd_in[69]
    DIRECTION INPUT ;
    USE SIGNAL ;
    SHAPE ABUTMENT ;
    PORT
      LAYER M4 ;
      RECT 0.000 49.680 0.024 49.704 ;
    END
  END wd_in[69]
  PIN wd_in[70]
    DIRECTION INPUT ;
    USE SIGNAL ;
    SHAPE ABUTMENT ;
    PORT
      LAYER M4 ;
      RECT 0.000 49.824 0.024 49.848 ;
    END
  END wd_in[70]
  PIN wd_in[71]
    DIRECTION INPUT ;
    USE SIGNAL ;
    SHAPE ABUTMENT ;
    PORT
      LAYER M4 ;
      RECT 0.000 49.968 0.024 49.992 ;
    END
  END wd_in[71]
  PIN wd_in[72]
    DIRECTION INPUT ;
    USE SIGNAL ;
    SHAPE ABUTMENT ;
    PORT
      LAYER M4 ;
      RECT 0.000 50.112 0.024 50.136 ;
    END
  END wd_in[72]
  PIN wd_in[73]
    DIRECTION INPUT ;
    USE SIGNAL ;
    SHAPE ABUTMENT ;
    PORT
      LAYER M4 ;
      RECT 0.000 50.256 0.024 50.280 ;
    END
  END wd_in[73]
  PIN wd_in[74]
    DIRECTION INPUT ;
    USE SIGNAL ;
    SHAPE ABUTMENT ;
    PORT
      LAYER M4 ;
      RECT 0.000 50.400 0.024 50.424 ;
    END
  END wd_in[74]
  PIN wd_in[75]
    DIRECTION INPUT ;
    USE SIGNAL ;
    SHAPE ABUTMENT ;
    PORT
      LAYER M4 ;
      RECT 0.000 50.544 0.024 50.568 ;
    END
  END wd_in[75]
  PIN wd_in[76]
    DIRECTION INPUT ;
    USE SIGNAL ;
    SHAPE ABUTMENT ;
    PORT
      LAYER M4 ;
      RECT 0.000 50.688 0.024 50.712 ;
    END
  END wd_in[76]
  PIN wd_in[77]
    DIRECTION INPUT ;
    USE SIGNAL ;
    SHAPE ABUTMENT ;
    PORT
      LAYER M4 ;
      RECT 0.000 50.832 0.024 50.856 ;
    END
  END wd_in[77]
  PIN wd_in[78]
    DIRECTION INPUT ;
    USE SIGNAL ;
    SHAPE ABUTMENT ;
    PORT
      LAYER M4 ;
      RECT 0.000 50.976 0.024 51.000 ;
    END
  END wd_in[78]
  PIN wd_in[79]
    DIRECTION INPUT ;
    USE SIGNAL ;
    SHAPE ABUTMENT ;
    PORT
      LAYER M4 ;
      RECT 0.000 51.120 0.024 51.144 ;
    END
  END wd_in[79]
  PIN wd_in[80]
    DIRECTION INPUT ;
    USE SIGNAL ;
    SHAPE ABUTMENT ;
    PORT
      LAYER M4 ;
      RECT 0.000 51.264 0.024 51.288 ;
    END
  END wd_in[80]
  PIN wd_in[81]
    DIRECTION INPUT ;
    USE SIGNAL ;
    SHAPE ABUTMENT ;
    PORT
      LAYER M4 ;
      RECT 0.000 51.408 0.024 51.432 ;
    END
  END wd_in[81]
  PIN wd_in[82]
    DIRECTION INPUT ;
    USE SIGNAL ;
    SHAPE ABUTMENT ;
    PORT
      LAYER M4 ;
      RECT 0.000 51.552 0.024 51.576 ;
    END
  END wd_in[82]
  PIN wd_in[83]
    DIRECTION INPUT ;
    USE SIGNAL ;
    SHAPE ABUTMENT ;
    PORT
      LAYER M4 ;
      RECT 0.000 51.696 0.024 51.720 ;
    END
  END wd_in[83]
  PIN wd_in[84]
    DIRECTION INPUT ;
    USE SIGNAL ;
    SHAPE ABUTMENT ;
    PORT
      LAYER M4 ;
      RECT 0.000 51.840 0.024 51.864 ;
    END
  END wd_in[84]
  PIN wd_in[85]
    DIRECTION INPUT ;
    USE SIGNAL ;
    SHAPE ABUTMENT ;
    PORT
      LAYER M4 ;
      RECT 0.000 51.984 0.024 52.008 ;
    END
  END wd_in[85]
  PIN wd_in[86]
    DIRECTION INPUT ;
    USE SIGNAL ;
    SHAPE ABUTMENT ;
    PORT
      LAYER M4 ;
      RECT 0.000 52.128 0.024 52.152 ;
    END
  END wd_in[86]
  PIN wd_in[87]
    DIRECTION INPUT ;
    USE SIGNAL ;
    SHAPE ABUTMENT ;
    PORT
      LAYER M4 ;
      RECT 0.000 52.272 0.024 52.296 ;
    END
  END wd_in[87]
  PIN wd_in[88]
    DIRECTION INPUT ;
    USE SIGNAL ;
    SHAPE ABUTMENT ;
    PORT
      LAYER M4 ;
      RECT 0.000 52.416 0.024 52.440 ;
    END
  END wd_in[88]
  PIN wd_in[89]
    DIRECTION INPUT ;
    USE SIGNAL ;
    SHAPE ABUTMENT ;
    PORT
      LAYER M4 ;
      RECT 0.000 52.560 0.024 52.584 ;
    END
  END wd_in[89]
  PIN wd_in[90]
    DIRECTION INPUT ;
    USE SIGNAL ;
    SHAPE ABUTMENT ;
    PORT
      LAYER M4 ;
      RECT 0.000 52.704 0.024 52.728 ;
    END
  END wd_in[90]
  PIN wd_in[91]
    DIRECTION INPUT ;
    USE SIGNAL ;
    SHAPE ABUTMENT ;
    PORT
      LAYER M4 ;
      RECT 0.000 52.848 0.024 52.872 ;
    END
  END wd_in[91]
  PIN wd_in[92]
    DIRECTION INPUT ;
    USE SIGNAL ;
    SHAPE ABUTMENT ;
    PORT
      LAYER M4 ;
      RECT 0.000 52.992 0.024 53.016 ;
    END
  END wd_in[92]
  PIN wd_in[93]
    DIRECTION INPUT ;
    USE SIGNAL ;
    SHAPE ABUTMENT ;
    PORT
      LAYER M4 ;
      RECT 0.000 53.136 0.024 53.160 ;
    END
  END wd_in[93]
  PIN wd_in[94]
    DIRECTION INPUT ;
    USE SIGNAL ;
    SHAPE ABUTMENT ;
    PORT
      LAYER M4 ;
      RECT 0.000 53.280 0.024 53.304 ;
    END
  END wd_in[94]
  PIN wd_in[95]
    DIRECTION INPUT ;
    USE SIGNAL ;
    SHAPE ABUTMENT ;
    PORT
      LAYER M4 ;
      RECT 0.000 53.424 0.024 53.448 ;
    END
  END wd_in[95]
  PIN wd_in[96]
    DIRECTION INPUT ;
    USE SIGNAL ;
    SHAPE ABUTMENT ;
    PORT
      LAYER M4 ;
      RECT 0.000 53.568 0.024 53.592 ;
    END
  END wd_in[96]
  PIN wd_in[97]
    DIRECTION INPUT ;
    USE SIGNAL ;
    SHAPE ABUTMENT ;
    PORT
      LAYER M4 ;
      RECT 0.000 53.712 0.024 53.736 ;
    END
  END wd_in[97]
  PIN wd_in[98]
    DIRECTION INPUT ;
    USE SIGNAL ;
    SHAPE ABUTMENT ;
    PORT
      LAYER M4 ;
      RECT 0.000 53.856 0.024 53.880 ;
    END
  END wd_in[98]
  PIN wd_in[99]
    DIRECTION INPUT ;
    USE SIGNAL ;
    SHAPE ABUTMENT ;
    PORT
      LAYER M4 ;
      RECT 0.000 54.000 0.024 54.024 ;
    END
  END wd_in[99]
  PIN wd_in[100]
    DIRECTION INPUT ;
    USE SIGNAL ;
    SHAPE ABUTMENT ;
    PORT
      LAYER M4 ;
      RECT 0.000 54.144 0.024 54.168 ;
    END
  END wd_in[100]
  PIN wd_in[101]
    DIRECTION INPUT ;
    USE SIGNAL ;
    SHAPE ABUTMENT ;
    PORT
      LAYER M4 ;
      RECT 0.000 54.288 0.024 54.312 ;
    END
  END wd_in[101]
  PIN wd_in[102]
    DIRECTION INPUT ;
    USE SIGNAL ;
    SHAPE ABUTMENT ;
    PORT
      LAYER M4 ;
      RECT 0.000 54.432 0.024 54.456 ;
    END
  END wd_in[102]
  PIN wd_in[103]
    DIRECTION INPUT ;
    USE SIGNAL ;
    SHAPE ABUTMENT ;
    PORT
      LAYER M4 ;
      RECT 0.000 54.576 0.024 54.600 ;
    END
  END wd_in[103]
  PIN wd_in[104]
    DIRECTION INPUT ;
    USE SIGNAL ;
    SHAPE ABUTMENT ;
    PORT
      LAYER M4 ;
      RECT 0.000 54.720 0.024 54.744 ;
    END
  END wd_in[104]
  PIN wd_in[105]
    DIRECTION INPUT ;
    USE SIGNAL ;
    SHAPE ABUTMENT ;
    PORT
      LAYER M4 ;
      RECT 0.000 54.864 0.024 54.888 ;
    END
  END wd_in[105]
  PIN wd_in[106]
    DIRECTION INPUT ;
    USE SIGNAL ;
    SHAPE ABUTMENT ;
    PORT
      LAYER M4 ;
      RECT 0.000 55.008 0.024 55.032 ;
    END
  END wd_in[106]
  PIN wd_in[107]
    DIRECTION INPUT ;
    USE SIGNAL ;
    SHAPE ABUTMENT ;
    PORT
      LAYER M4 ;
      RECT 0.000 55.152 0.024 55.176 ;
    END
  END wd_in[107]
  PIN wd_in[108]
    DIRECTION INPUT ;
    USE SIGNAL ;
    SHAPE ABUTMENT ;
    PORT
      LAYER M4 ;
      RECT 0.000 55.296 0.024 55.320 ;
    END
  END wd_in[108]
  PIN wd_in[109]
    DIRECTION INPUT ;
    USE SIGNAL ;
    SHAPE ABUTMENT ;
    PORT
      LAYER M4 ;
      RECT 0.000 55.440 0.024 55.464 ;
    END
  END wd_in[109]
  PIN wd_in[110]
    DIRECTION INPUT ;
    USE SIGNAL ;
    SHAPE ABUTMENT ;
    PORT
      LAYER M4 ;
      RECT 0.000 55.584 0.024 55.608 ;
    END
  END wd_in[110]
  PIN wd_in[111]
    DIRECTION INPUT ;
    USE SIGNAL ;
    SHAPE ABUTMENT ;
    PORT
      LAYER M4 ;
      RECT 0.000 55.728 0.024 55.752 ;
    END
  END wd_in[111]
  PIN wd_in[112]
    DIRECTION INPUT ;
    USE SIGNAL ;
    SHAPE ABUTMENT ;
    PORT
      LAYER M4 ;
      RECT 0.000 55.872 0.024 55.896 ;
    END
  END wd_in[112]
  PIN wd_in[113]
    DIRECTION INPUT ;
    USE SIGNAL ;
    SHAPE ABUTMENT ;
    PORT
      LAYER M4 ;
      RECT 0.000 56.016 0.024 56.040 ;
    END
  END wd_in[113]
  PIN wd_in[114]
    DIRECTION INPUT ;
    USE SIGNAL ;
    SHAPE ABUTMENT ;
    PORT
      LAYER M4 ;
      RECT 0.000 56.160 0.024 56.184 ;
    END
  END wd_in[114]
  PIN wd_in[115]
    DIRECTION INPUT ;
    USE SIGNAL ;
    SHAPE ABUTMENT ;
    PORT
      LAYER M4 ;
      RECT 0.000 56.304 0.024 56.328 ;
    END
  END wd_in[115]
  PIN wd_in[116]
    DIRECTION INPUT ;
    USE SIGNAL ;
    SHAPE ABUTMENT ;
    PORT
      LAYER M4 ;
      RECT 0.000 56.448 0.024 56.472 ;
    END
  END wd_in[116]
  PIN wd_in[117]
    DIRECTION INPUT ;
    USE SIGNAL ;
    SHAPE ABUTMENT ;
    PORT
      LAYER M4 ;
      RECT 0.000 56.592 0.024 56.616 ;
    END
  END wd_in[117]
  PIN wd_in[118]
    DIRECTION INPUT ;
    USE SIGNAL ;
    SHAPE ABUTMENT ;
    PORT
      LAYER M4 ;
      RECT 0.000 56.736 0.024 56.760 ;
    END
  END wd_in[118]
  PIN wd_in[119]
    DIRECTION INPUT ;
    USE SIGNAL ;
    SHAPE ABUTMENT ;
    PORT
      LAYER M4 ;
      RECT 0.000 56.880 0.024 56.904 ;
    END
  END wd_in[119]
  PIN wd_in[120]
    DIRECTION INPUT ;
    USE SIGNAL ;
    SHAPE ABUTMENT ;
    PORT
      LAYER M4 ;
      RECT 0.000 57.024 0.024 57.048 ;
    END
  END wd_in[120]
  PIN wd_in[121]
    DIRECTION INPUT ;
    USE SIGNAL ;
    SHAPE ABUTMENT ;
    PORT
      LAYER M4 ;
      RECT 0.000 57.168 0.024 57.192 ;
    END
  END wd_in[121]
  PIN wd_in[122]
    DIRECTION INPUT ;
    USE SIGNAL ;
    SHAPE ABUTMENT ;
    PORT
      LAYER M4 ;
      RECT 0.000 57.312 0.024 57.336 ;
    END
  END wd_in[122]
  PIN wd_in[123]
    DIRECTION INPUT ;
    USE SIGNAL ;
    SHAPE ABUTMENT ;
    PORT
      LAYER M4 ;
      RECT 0.000 57.456 0.024 57.480 ;
    END
  END wd_in[123]
  PIN wd_in[124]
    DIRECTION INPUT ;
    USE SIGNAL ;
    SHAPE ABUTMENT ;
    PORT
      LAYER M4 ;
      RECT 0.000 57.600 0.024 57.624 ;
    END
  END wd_in[124]
  PIN wd_in[125]
    DIRECTION INPUT ;
    USE SIGNAL ;
    SHAPE ABUTMENT ;
    PORT
      LAYER M4 ;
      RECT 0.000 57.744 0.024 57.768 ;
    END
  END wd_in[125]
  PIN wd_in[126]
    DIRECTION INPUT ;
    USE SIGNAL ;
    SHAPE ABUTMENT ;
    PORT
      LAYER M4 ;
      RECT 0.000 57.888 0.024 57.912 ;
    END
  END wd_in[126]
  PIN wd_in[127]
    DIRECTION INPUT ;
    USE SIGNAL ;
    SHAPE ABUTMENT ;
    PORT
      LAYER M4 ;
      RECT 0.000 58.032 0.024 58.056 ;
    END
  END wd_in[127]
  PIN wd_in[128]
    DIRECTION INPUT ;
    USE SIGNAL ;
    SHAPE ABUTMENT ;
    PORT
      LAYER M4 ;
      RECT 0.000 58.176 0.024 58.200 ;
    END
  END wd_in[128]
  PIN wd_in[129]
    DIRECTION INPUT ;
    USE SIGNAL ;
    SHAPE ABUTMENT ;
    PORT
      LAYER M4 ;
      RECT 0.000 58.320 0.024 58.344 ;
    END
  END wd_in[129]
  PIN wd_in[130]
    DIRECTION INPUT ;
    USE SIGNAL ;
    SHAPE ABUTMENT ;
    PORT
      LAYER M4 ;
      RECT 0.000 58.464 0.024 58.488 ;
    END
  END wd_in[130]
  PIN wd_in[131]
    DIRECTION INPUT ;
    USE SIGNAL ;
    SHAPE ABUTMENT ;
    PORT
      LAYER M4 ;
      RECT 0.000 58.608 0.024 58.632 ;
    END
  END wd_in[131]
  PIN wd_in[132]
    DIRECTION INPUT ;
    USE SIGNAL ;
    SHAPE ABUTMENT ;
    PORT
      LAYER M4 ;
      RECT 0.000 58.752 0.024 58.776 ;
    END
  END wd_in[132]
  PIN wd_in[133]
    DIRECTION INPUT ;
    USE SIGNAL ;
    SHAPE ABUTMENT ;
    PORT
      LAYER M4 ;
      RECT 0.000 58.896 0.024 58.920 ;
    END
  END wd_in[133]
  PIN wd_in[134]
    DIRECTION INPUT ;
    USE SIGNAL ;
    SHAPE ABUTMENT ;
    PORT
      LAYER M4 ;
      RECT 0.000 59.040 0.024 59.064 ;
    END
  END wd_in[134]
  PIN wd_in[135]
    DIRECTION INPUT ;
    USE SIGNAL ;
    SHAPE ABUTMENT ;
    PORT
      LAYER M4 ;
      RECT 0.000 59.184 0.024 59.208 ;
    END
  END wd_in[135]
  PIN wd_in[136]
    DIRECTION INPUT ;
    USE SIGNAL ;
    SHAPE ABUTMENT ;
    PORT
      LAYER M4 ;
      RECT 0.000 59.328 0.024 59.352 ;
    END
  END wd_in[136]
  PIN wd_in[137]
    DIRECTION INPUT ;
    USE SIGNAL ;
    SHAPE ABUTMENT ;
    PORT
      LAYER M4 ;
      RECT 0.000 59.472 0.024 59.496 ;
    END
  END wd_in[137]
  PIN wd_in[138]
    DIRECTION INPUT ;
    USE SIGNAL ;
    SHAPE ABUTMENT ;
    PORT
      LAYER M4 ;
      RECT 0.000 59.616 0.024 59.640 ;
    END
  END wd_in[138]
  PIN wd_in[139]
    DIRECTION INPUT ;
    USE SIGNAL ;
    SHAPE ABUTMENT ;
    PORT
      LAYER M4 ;
      RECT 0.000 59.760 0.024 59.784 ;
    END
  END wd_in[139]
  PIN wd_in[140]
    DIRECTION INPUT ;
    USE SIGNAL ;
    SHAPE ABUTMENT ;
    PORT
      LAYER M4 ;
      RECT 0.000 59.904 0.024 59.928 ;
    END
  END wd_in[140]
  PIN wd_in[141]
    DIRECTION INPUT ;
    USE SIGNAL ;
    SHAPE ABUTMENT ;
    PORT
      LAYER M4 ;
      RECT 0.000 60.048 0.024 60.072 ;
    END
  END wd_in[141]
  PIN wd_in[142]
    DIRECTION INPUT ;
    USE SIGNAL ;
    SHAPE ABUTMENT ;
    PORT
      LAYER M4 ;
      RECT 0.000 60.192 0.024 60.216 ;
    END
  END wd_in[142]
  PIN wd_in[143]
    DIRECTION INPUT ;
    USE SIGNAL ;
    SHAPE ABUTMENT ;
    PORT
      LAYER M4 ;
      RECT 0.000 60.336 0.024 60.360 ;
    END
  END wd_in[143]
  PIN wd_in[144]
    DIRECTION INPUT ;
    USE SIGNAL ;
    SHAPE ABUTMENT ;
    PORT
      LAYER M4 ;
      RECT 0.000 60.480 0.024 60.504 ;
    END
  END wd_in[144]
  PIN wd_in[145]
    DIRECTION INPUT ;
    USE SIGNAL ;
    SHAPE ABUTMENT ;
    PORT
      LAYER M4 ;
      RECT 0.000 60.624 0.024 60.648 ;
    END
  END wd_in[145]
  PIN wd_in[146]
    DIRECTION INPUT ;
    USE SIGNAL ;
    SHAPE ABUTMENT ;
    PORT
      LAYER M4 ;
      RECT 0.000 60.768 0.024 60.792 ;
    END
  END wd_in[146]
  PIN wd_in[147]
    DIRECTION INPUT ;
    USE SIGNAL ;
    SHAPE ABUTMENT ;
    PORT
      LAYER M4 ;
      RECT 0.000 60.912 0.024 60.936 ;
    END
  END wd_in[147]
  PIN wd_in[148]
    DIRECTION INPUT ;
    USE SIGNAL ;
    SHAPE ABUTMENT ;
    PORT
      LAYER M4 ;
      RECT 0.000 61.056 0.024 61.080 ;
    END
  END wd_in[148]
  PIN wd_in[149]
    DIRECTION INPUT ;
    USE SIGNAL ;
    SHAPE ABUTMENT ;
    PORT
      LAYER M4 ;
      RECT 0.000 61.200 0.024 61.224 ;
    END
  END wd_in[149]
  PIN wd_in[150]
    DIRECTION INPUT ;
    USE SIGNAL ;
    SHAPE ABUTMENT ;
    PORT
      LAYER M4 ;
      RECT 0.000 61.344 0.024 61.368 ;
    END
  END wd_in[150]
  PIN wd_in[151]
    DIRECTION INPUT ;
    USE SIGNAL ;
    SHAPE ABUTMENT ;
    PORT
      LAYER M4 ;
      RECT 0.000 61.488 0.024 61.512 ;
    END
  END wd_in[151]
  PIN wd_in[152]
    DIRECTION INPUT ;
    USE SIGNAL ;
    SHAPE ABUTMENT ;
    PORT
      LAYER M4 ;
      RECT 0.000 61.632 0.024 61.656 ;
    END
  END wd_in[152]
  PIN wd_in[153]
    DIRECTION INPUT ;
    USE SIGNAL ;
    SHAPE ABUTMENT ;
    PORT
      LAYER M4 ;
      RECT 0.000 61.776 0.024 61.800 ;
    END
  END wd_in[153]
  PIN wd_in[154]
    DIRECTION INPUT ;
    USE SIGNAL ;
    SHAPE ABUTMENT ;
    PORT
      LAYER M4 ;
      RECT 0.000 61.920 0.024 61.944 ;
    END
  END wd_in[154]
  PIN wd_in[155]
    DIRECTION INPUT ;
    USE SIGNAL ;
    SHAPE ABUTMENT ;
    PORT
      LAYER M4 ;
      RECT 0.000 62.064 0.024 62.088 ;
    END
  END wd_in[155]
  PIN wd_in[156]
    DIRECTION INPUT ;
    USE SIGNAL ;
    SHAPE ABUTMENT ;
    PORT
      LAYER M4 ;
      RECT 0.000 62.208 0.024 62.232 ;
    END
  END wd_in[156]
  PIN wd_in[157]
    DIRECTION INPUT ;
    USE SIGNAL ;
    SHAPE ABUTMENT ;
    PORT
      LAYER M4 ;
      RECT 0.000 62.352 0.024 62.376 ;
    END
  END wd_in[157]
  PIN wd_in[158]
    DIRECTION INPUT ;
    USE SIGNAL ;
    SHAPE ABUTMENT ;
    PORT
      LAYER M4 ;
      RECT 0.000 62.496 0.024 62.520 ;
    END
  END wd_in[158]
  PIN wd_in[159]
    DIRECTION INPUT ;
    USE SIGNAL ;
    SHAPE ABUTMENT ;
    PORT
      LAYER M4 ;
      RECT 0.000 62.640 0.024 62.664 ;
    END
  END wd_in[159]
  PIN wd_in[160]
    DIRECTION INPUT ;
    USE SIGNAL ;
    SHAPE ABUTMENT ;
    PORT
      LAYER M4 ;
      RECT 0.000 62.784 0.024 62.808 ;
    END
  END wd_in[160]
  PIN wd_in[161]
    DIRECTION INPUT ;
    USE SIGNAL ;
    SHAPE ABUTMENT ;
    PORT
      LAYER M4 ;
      RECT 0.000 62.928 0.024 62.952 ;
    END
  END wd_in[161]
  PIN wd_in[162]
    DIRECTION INPUT ;
    USE SIGNAL ;
    SHAPE ABUTMENT ;
    PORT
      LAYER M4 ;
      RECT 0.000 63.072 0.024 63.096 ;
    END
  END wd_in[162]
  PIN wd_in[163]
    DIRECTION INPUT ;
    USE SIGNAL ;
    SHAPE ABUTMENT ;
    PORT
      LAYER M4 ;
      RECT 0.000 63.216 0.024 63.240 ;
    END
  END wd_in[163]
  PIN wd_in[164]
    DIRECTION INPUT ;
    USE SIGNAL ;
    SHAPE ABUTMENT ;
    PORT
      LAYER M4 ;
      RECT 0.000 63.360 0.024 63.384 ;
    END
  END wd_in[164]
  PIN wd_in[165]
    DIRECTION INPUT ;
    USE SIGNAL ;
    SHAPE ABUTMENT ;
    PORT
      LAYER M4 ;
      RECT 0.000 63.504 0.024 63.528 ;
    END
  END wd_in[165]
  PIN wd_in[166]
    DIRECTION INPUT ;
    USE SIGNAL ;
    SHAPE ABUTMENT ;
    PORT
      LAYER M4 ;
      RECT 0.000 63.648 0.024 63.672 ;
    END
  END wd_in[166]
  PIN wd_in[167]
    DIRECTION INPUT ;
    USE SIGNAL ;
    SHAPE ABUTMENT ;
    PORT
      LAYER M4 ;
      RECT 0.000 63.792 0.024 63.816 ;
    END
  END wd_in[167]
  PIN wd_in[168]
    DIRECTION INPUT ;
    USE SIGNAL ;
    SHAPE ABUTMENT ;
    PORT
      LAYER M4 ;
      RECT 0.000 63.936 0.024 63.960 ;
    END
  END wd_in[168]
  PIN wd_in[169]
    DIRECTION INPUT ;
    USE SIGNAL ;
    SHAPE ABUTMENT ;
    PORT
      LAYER M4 ;
      RECT 0.000 64.080 0.024 64.104 ;
    END
  END wd_in[169]
  PIN wd_in[170]
    DIRECTION INPUT ;
    USE SIGNAL ;
    SHAPE ABUTMENT ;
    PORT
      LAYER M4 ;
      RECT 0.000 64.224 0.024 64.248 ;
    END
  END wd_in[170]
  PIN wd_in[171]
    DIRECTION INPUT ;
    USE SIGNAL ;
    SHAPE ABUTMENT ;
    PORT
      LAYER M4 ;
      RECT 0.000 64.368 0.024 64.392 ;
    END
  END wd_in[171]
  PIN wd_in[172]
    DIRECTION INPUT ;
    USE SIGNAL ;
    SHAPE ABUTMENT ;
    PORT
      LAYER M4 ;
      RECT 0.000 64.512 0.024 64.536 ;
    END
  END wd_in[172]
  PIN wd_in[173]
    DIRECTION INPUT ;
    USE SIGNAL ;
    SHAPE ABUTMENT ;
    PORT
      LAYER M4 ;
      RECT 0.000 64.656 0.024 64.680 ;
    END
  END wd_in[173]
  PIN wd_in[174]
    DIRECTION INPUT ;
    USE SIGNAL ;
    SHAPE ABUTMENT ;
    PORT
      LAYER M4 ;
      RECT 0.000 64.800 0.024 64.824 ;
    END
  END wd_in[174]
  PIN wd_in[175]
    DIRECTION INPUT ;
    USE SIGNAL ;
    SHAPE ABUTMENT ;
    PORT
      LAYER M4 ;
      RECT 0.000 64.944 0.024 64.968 ;
    END
  END wd_in[175]
  PIN wd_in[176]
    DIRECTION INPUT ;
    USE SIGNAL ;
    SHAPE ABUTMENT ;
    PORT
      LAYER M4 ;
      RECT 0.000 65.088 0.024 65.112 ;
    END
  END wd_in[176]
  PIN wd_in[177]
    DIRECTION INPUT ;
    USE SIGNAL ;
    SHAPE ABUTMENT ;
    PORT
      LAYER M4 ;
      RECT 0.000 65.232 0.024 65.256 ;
    END
  END wd_in[177]
  PIN wd_in[178]
    DIRECTION INPUT ;
    USE SIGNAL ;
    SHAPE ABUTMENT ;
    PORT
      LAYER M4 ;
      RECT 0.000 65.376 0.024 65.400 ;
    END
  END wd_in[178]
  PIN wd_in[179]
    DIRECTION INPUT ;
    USE SIGNAL ;
    SHAPE ABUTMENT ;
    PORT
      LAYER M4 ;
      RECT 0.000 65.520 0.024 65.544 ;
    END
  END wd_in[179]
  PIN wd_in[180]
    DIRECTION INPUT ;
    USE SIGNAL ;
    SHAPE ABUTMENT ;
    PORT
      LAYER M4 ;
      RECT 0.000 65.664 0.024 65.688 ;
    END
  END wd_in[180]
  PIN wd_in[181]
    DIRECTION INPUT ;
    USE SIGNAL ;
    SHAPE ABUTMENT ;
    PORT
      LAYER M4 ;
      RECT 0.000 65.808 0.024 65.832 ;
    END
  END wd_in[181]
  PIN wd_in[182]
    DIRECTION INPUT ;
    USE SIGNAL ;
    SHAPE ABUTMENT ;
    PORT
      LAYER M4 ;
      RECT 0.000 65.952 0.024 65.976 ;
    END
  END wd_in[182]
  PIN wd_in[183]
    DIRECTION INPUT ;
    USE SIGNAL ;
    SHAPE ABUTMENT ;
    PORT
      LAYER M4 ;
      RECT 0.000 66.096 0.024 66.120 ;
    END
  END wd_in[183]
  PIN wd_in[184]
    DIRECTION INPUT ;
    USE SIGNAL ;
    SHAPE ABUTMENT ;
    PORT
      LAYER M4 ;
      RECT 0.000 66.240 0.024 66.264 ;
    END
  END wd_in[184]
  PIN wd_in[185]
    DIRECTION INPUT ;
    USE SIGNAL ;
    SHAPE ABUTMENT ;
    PORT
      LAYER M4 ;
      RECT 0.000 66.384 0.024 66.408 ;
    END
  END wd_in[185]
  PIN wd_in[186]
    DIRECTION INPUT ;
    USE SIGNAL ;
    SHAPE ABUTMENT ;
    PORT
      LAYER M4 ;
      RECT 0.000 66.528 0.024 66.552 ;
    END
  END wd_in[186]
  PIN wd_in[187]
    DIRECTION INPUT ;
    USE SIGNAL ;
    SHAPE ABUTMENT ;
    PORT
      LAYER M4 ;
      RECT 0.000 66.672 0.024 66.696 ;
    END
  END wd_in[187]
  PIN wd_in[188]
    DIRECTION INPUT ;
    USE SIGNAL ;
    SHAPE ABUTMENT ;
    PORT
      LAYER M4 ;
      RECT 0.000 66.816 0.024 66.840 ;
    END
  END wd_in[188]
  PIN wd_in[189]
    DIRECTION INPUT ;
    USE SIGNAL ;
    SHAPE ABUTMENT ;
    PORT
      LAYER M4 ;
      RECT 0.000 66.960 0.024 66.984 ;
    END
  END wd_in[189]
  PIN wd_in[190]
    DIRECTION INPUT ;
    USE SIGNAL ;
    SHAPE ABUTMENT ;
    PORT
      LAYER M4 ;
      RECT 0.000 67.104 0.024 67.128 ;
    END
  END wd_in[190]
  PIN wd_in[191]
    DIRECTION INPUT ;
    USE SIGNAL ;
    SHAPE ABUTMENT ;
    PORT
      LAYER M4 ;
      RECT 0.000 67.248 0.024 67.272 ;
    END
  END wd_in[191]
  PIN wd_in[192]
    DIRECTION INPUT ;
    USE SIGNAL ;
    SHAPE ABUTMENT ;
    PORT
      LAYER M4 ;
      RECT 0.000 67.392 0.024 67.416 ;
    END
  END wd_in[192]
  PIN wd_in[193]
    DIRECTION INPUT ;
    USE SIGNAL ;
    SHAPE ABUTMENT ;
    PORT
      LAYER M4 ;
      RECT 0.000 67.536 0.024 67.560 ;
    END
  END wd_in[193]
  PIN wd_in[194]
    DIRECTION INPUT ;
    USE SIGNAL ;
    SHAPE ABUTMENT ;
    PORT
      LAYER M4 ;
      RECT 0.000 67.680 0.024 67.704 ;
    END
  END wd_in[194]
  PIN wd_in[195]
    DIRECTION INPUT ;
    USE SIGNAL ;
    SHAPE ABUTMENT ;
    PORT
      LAYER M4 ;
      RECT 0.000 67.824 0.024 67.848 ;
    END
  END wd_in[195]
  PIN wd_in[196]
    DIRECTION INPUT ;
    USE SIGNAL ;
    SHAPE ABUTMENT ;
    PORT
      LAYER M4 ;
      RECT 0.000 67.968 0.024 67.992 ;
    END
  END wd_in[196]
  PIN wd_in[197]
    DIRECTION INPUT ;
    USE SIGNAL ;
    SHAPE ABUTMENT ;
    PORT
      LAYER M4 ;
      RECT 0.000 68.112 0.024 68.136 ;
    END
  END wd_in[197]
  PIN wd_in[198]
    DIRECTION INPUT ;
    USE SIGNAL ;
    SHAPE ABUTMENT ;
    PORT
      LAYER M4 ;
      RECT 0.000 68.256 0.024 68.280 ;
    END
  END wd_in[198]
  PIN wd_in[199]
    DIRECTION INPUT ;
    USE SIGNAL ;
    SHAPE ABUTMENT ;
    PORT
      LAYER M4 ;
      RECT 0.000 68.400 0.024 68.424 ;
    END
  END wd_in[199]
  PIN wd_in[200]
    DIRECTION INPUT ;
    USE SIGNAL ;
    SHAPE ABUTMENT ;
    PORT
      LAYER M4 ;
      RECT 0.000 68.544 0.024 68.568 ;
    END
  END wd_in[200]
  PIN wd_in[201]
    DIRECTION INPUT ;
    USE SIGNAL ;
    SHAPE ABUTMENT ;
    PORT
      LAYER M4 ;
      RECT 0.000 68.688 0.024 68.712 ;
    END
  END wd_in[201]
  PIN wd_in[202]
    DIRECTION INPUT ;
    USE SIGNAL ;
    SHAPE ABUTMENT ;
    PORT
      LAYER M4 ;
      RECT 0.000 68.832 0.024 68.856 ;
    END
  END wd_in[202]
  PIN wd_in[203]
    DIRECTION INPUT ;
    USE SIGNAL ;
    SHAPE ABUTMENT ;
    PORT
      LAYER M4 ;
      RECT 0.000 68.976 0.024 69.000 ;
    END
  END wd_in[203]
  PIN wd_in[204]
    DIRECTION INPUT ;
    USE SIGNAL ;
    SHAPE ABUTMENT ;
    PORT
      LAYER M4 ;
      RECT 0.000 69.120 0.024 69.144 ;
    END
  END wd_in[204]
  PIN wd_in[205]
    DIRECTION INPUT ;
    USE SIGNAL ;
    SHAPE ABUTMENT ;
    PORT
      LAYER M4 ;
      RECT 0.000 69.264 0.024 69.288 ;
    END
  END wd_in[205]
  PIN wd_in[206]
    DIRECTION INPUT ;
    USE SIGNAL ;
    SHAPE ABUTMENT ;
    PORT
      LAYER M4 ;
      RECT 0.000 69.408 0.024 69.432 ;
    END
  END wd_in[206]
  PIN wd_in[207]
    DIRECTION INPUT ;
    USE SIGNAL ;
    SHAPE ABUTMENT ;
    PORT
      LAYER M4 ;
      RECT 0.000 69.552 0.024 69.576 ;
    END
  END wd_in[207]
  PIN wd_in[208]
    DIRECTION INPUT ;
    USE SIGNAL ;
    SHAPE ABUTMENT ;
    PORT
      LAYER M4 ;
      RECT 0.000 69.696 0.024 69.720 ;
    END
  END wd_in[208]
  PIN wd_in[209]
    DIRECTION INPUT ;
    USE SIGNAL ;
    SHAPE ABUTMENT ;
    PORT
      LAYER M4 ;
      RECT 0.000 69.840 0.024 69.864 ;
    END
  END wd_in[209]
  PIN wd_in[210]
    DIRECTION INPUT ;
    USE SIGNAL ;
    SHAPE ABUTMENT ;
    PORT
      LAYER M4 ;
      RECT 0.000 69.984 0.024 70.008 ;
    END
  END wd_in[210]
  PIN wd_in[211]
    DIRECTION INPUT ;
    USE SIGNAL ;
    SHAPE ABUTMENT ;
    PORT
      LAYER M4 ;
      RECT 0.000 70.128 0.024 70.152 ;
    END
  END wd_in[211]
  PIN wd_in[212]
    DIRECTION INPUT ;
    USE SIGNAL ;
    SHAPE ABUTMENT ;
    PORT
      LAYER M4 ;
      RECT 0.000 70.272 0.024 70.296 ;
    END
  END wd_in[212]
  PIN wd_in[213]
    DIRECTION INPUT ;
    USE SIGNAL ;
    SHAPE ABUTMENT ;
    PORT
      LAYER M4 ;
      RECT 0.000 70.416 0.024 70.440 ;
    END
  END wd_in[213]
  PIN wd_in[214]
    DIRECTION INPUT ;
    USE SIGNAL ;
    SHAPE ABUTMENT ;
    PORT
      LAYER M4 ;
      RECT 0.000 70.560 0.024 70.584 ;
    END
  END wd_in[214]
  PIN wd_in[215]
    DIRECTION INPUT ;
    USE SIGNAL ;
    SHAPE ABUTMENT ;
    PORT
      LAYER M4 ;
      RECT 0.000 70.704 0.024 70.728 ;
    END
  END wd_in[215]
  PIN wd_in[216]
    DIRECTION INPUT ;
    USE SIGNAL ;
    SHAPE ABUTMENT ;
    PORT
      LAYER M4 ;
      RECT 0.000 70.848 0.024 70.872 ;
    END
  END wd_in[216]
  PIN wd_in[217]
    DIRECTION INPUT ;
    USE SIGNAL ;
    SHAPE ABUTMENT ;
    PORT
      LAYER M4 ;
      RECT 0.000 70.992 0.024 71.016 ;
    END
  END wd_in[217]
  PIN wd_in[218]
    DIRECTION INPUT ;
    USE SIGNAL ;
    SHAPE ABUTMENT ;
    PORT
      LAYER M4 ;
      RECT 0.000 71.136 0.024 71.160 ;
    END
  END wd_in[218]
  PIN wd_in[219]
    DIRECTION INPUT ;
    USE SIGNAL ;
    SHAPE ABUTMENT ;
    PORT
      LAYER M4 ;
      RECT 0.000 71.280 0.024 71.304 ;
    END
  END wd_in[219]
  PIN wd_in[220]
    DIRECTION INPUT ;
    USE SIGNAL ;
    SHAPE ABUTMENT ;
    PORT
      LAYER M4 ;
      RECT 0.000 71.424 0.024 71.448 ;
    END
  END wd_in[220]
  PIN wd_in[221]
    DIRECTION INPUT ;
    USE SIGNAL ;
    SHAPE ABUTMENT ;
    PORT
      LAYER M4 ;
      RECT 0.000 71.568 0.024 71.592 ;
    END
  END wd_in[221]
  PIN wd_in[222]
    DIRECTION INPUT ;
    USE SIGNAL ;
    SHAPE ABUTMENT ;
    PORT
      LAYER M4 ;
      RECT 0.000 71.712 0.024 71.736 ;
    END
  END wd_in[222]
  PIN wd_in[223]
    DIRECTION INPUT ;
    USE SIGNAL ;
    SHAPE ABUTMENT ;
    PORT
      LAYER M4 ;
      RECT 0.000 71.856 0.024 71.880 ;
    END
  END wd_in[223]
  PIN wd_in[224]
    DIRECTION INPUT ;
    USE SIGNAL ;
    SHAPE ABUTMENT ;
    PORT
      LAYER M4 ;
      RECT 0.000 72.000 0.024 72.024 ;
    END
  END wd_in[224]
  PIN wd_in[225]
    DIRECTION INPUT ;
    USE SIGNAL ;
    SHAPE ABUTMENT ;
    PORT
      LAYER M4 ;
      RECT 0.000 72.144 0.024 72.168 ;
    END
  END wd_in[225]
  PIN wd_in[226]
    DIRECTION INPUT ;
    USE SIGNAL ;
    SHAPE ABUTMENT ;
    PORT
      LAYER M4 ;
      RECT 0.000 72.288 0.024 72.312 ;
    END
  END wd_in[226]
  PIN wd_in[227]
    DIRECTION INPUT ;
    USE SIGNAL ;
    SHAPE ABUTMENT ;
    PORT
      LAYER M4 ;
      RECT 0.000 72.432 0.024 72.456 ;
    END
  END wd_in[227]
  PIN wd_in[228]
    DIRECTION INPUT ;
    USE SIGNAL ;
    SHAPE ABUTMENT ;
    PORT
      LAYER M4 ;
      RECT 0.000 72.576 0.024 72.600 ;
    END
  END wd_in[228]
  PIN wd_in[229]
    DIRECTION INPUT ;
    USE SIGNAL ;
    SHAPE ABUTMENT ;
    PORT
      LAYER M4 ;
      RECT 0.000 72.720 0.024 72.744 ;
    END
  END wd_in[229]
  PIN wd_in[230]
    DIRECTION INPUT ;
    USE SIGNAL ;
    SHAPE ABUTMENT ;
    PORT
      LAYER M4 ;
      RECT 0.000 72.864 0.024 72.888 ;
    END
  END wd_in[230]
  PIN wd_in[231]
    DIRECTION INPUT ;
    USE SIGNAL ;
    SHAPE ABUTMENT ;
    PORT
      LAYER M4 ;
      RECT 0.000 73.008 0.024 73.032 ;
    END
  END wd_in[231]
  PIN wd_in[232]
    DIRECTION INPUT ;
    USE SIGNAL ;
    SHAPE ABUTMENT ;
    PORT
      LAYER M4 ;
      RECT 0.000 73.152 0.024 73.176 ;
    END
  END wd_in[232]
  PIN wd_in[233]
    DIRECTION INPUT ;
    USE SIGNAL ;
    SHAPE ABUTMENT ;
    PORT
      LAYER M4 ;
      RECT 0.000 73.296 0.024 73.320 ;
    END
  END wd_in[233]
  PIN wd_in[234]
    DIRECTION INPUT ;
    USE SIGNAL ;
    SHAPE ABUTMENT ;
    PORT
      LAYER M4 ;
      RECT 0.000 73.440 0.024 73.464 ;
    END
  END wd_in[234]
  PIN wd_in[235]
    DIRECTION INPUT ;
    USE SIGNAL ;
    SHAPE ABUTMENT ;
    PORT
      LAYER M4 ;
      RECT 0.000 73.584 0.024 73.608 ;
    END
  END wd_in[235]
  PIN wd_in[236]
    DIRECTION INPUT ;
    USE SIGNAL ;
    SHAPE ABUTMENT ;
    PORT
      LAYER M4 ;
      RECT 0.000 73.728 0.024 73.752 ;
    END
  END wd_in[236]
  PIN wd_in[237]
    DIRECTION INPUT ;
    USE SIGNAL ;
    SHAPE ABUTMENT ;
    PORT
      LAYER M4 ;
      RECT 0.000 73.872 0.024 73.896 ;
    END
  END wd_in[237]
  PIN wd_in[238]
    DIRECTION INPUT ;
    USE SIGNAL ;
    SHAPE ABUTMENT ;
    PORT
      LAYER M4 ;
      RECT 0.000 74.016 0.024 74.040 ;
    END
  END wd_in[238]
  PIN wd_in[239]
    DIRECTION INPUT ;
    USE SIGNAL ;
    SHAPE ABUTMENT ;
    PORT
      LAYER M4 ;
      RECT 0.000 74.160 0.024 74.184 ;
    END
  END wd_in[239]
  PIN wd_in[240]
    DIRECTION INPUT ;
    USE SIGNAL ;
    SHAPE ABUTMENT ;
    PORT
      LAYER M4 ;
      RECT 0.000 74.304 0.024 74.328 ;
    END
  END wd_in[240]
  PIN wd_in[241]
    DIRECTION INPUT ;
    USE SIGNAL ;
    SHAPE ABUTMENT ;
    PORT
      LAYER M4 ;
      RECT 0.000 74.448 0.024 74.472 ;
    END
  END wd_in[241]
  PIN wd_in[242]
    DIRECTION INPUT ;
    USE SIGNAL ;
    SHAPE ABUTMENT ;
    PORT
      LAYER M4 ;
      RECT 0.000 74.592 0.024 74.616 ;
    END
  END wd_in[242]
  PIN wd_in[243]
    DIRECTION INPUT ;
    USE SIGNAL ;
    SHAPE ABUTMENT ;
    PORT
      LAYER M4 ;
      RECT 0.000 74.736 0.024 74.760 ;
    END
  END wd_in[243]
  PIN wd_in[244]
    DIRECTION INPUT ;
    USE SIGNAL ;
    SHAPE ABUTMENT ;
    PORT
      LAYER M4 ;
      RECT 0.000 74.880 0.024 74.904 ;
    END
  END wd_in[244]
  PIN wd_in[245]
    DIRECTION INPUT ;
    USE SIGNAL ;
    SHAPE ABUTMENT ;
    PORT
      LAYER M4 ;
      RECT 0.000 75.024 0.024 75.048 ;
    END
  END wd_in[245]
  PIN wd_in[246]
    DIRECTION INPUT ;
    USE SIGNAL ;
    SHAPE ABUTMENT ;
    PORT
      LAYER M4 ;
      RECT 0.000 75.168 0.024 75.192 ;
    END
  END wd_in[246]
  PIN wd_in[247]
    DIRECTION INPUT ;
    USE SIGNAL ;
    SHAPE ABUTMENT ;
    PORT
      LAYER M4 ;
      RECT 0.000 75.312 0.024 75.336 ;
    END
  END wd_in[247]
  PIN wd_in[248]
    DIRECTION INPUT ;
    USE SIGNAL ;
    SHAPE ABUTMENT ;
    PORT
      LAYER M4 ;
      RECT 0.000 75.456 0.024 75.480 ;
    END
  END wd_in[248]
  PIN wd_in[249]
    DIRECTION INPUT ;
    USE SIGNAL ;
    SHAPE ABUTMENT ;
    PORT
      LAYER M4 ;
      RECT 0.000 75.600 0.024 75.624 ;
    END
  END wd_in[249]
  PIN wd_in[250]
    DIRECTION INPUT ;
    USE SIGNAL ;
    SHAPE ABUTMENT ;
    PORT
      LAYER M4 ;
      RECT 0.000 75.744 0.024 75.768 ;
    END
  END wd_in[250]
  PIN wd_in[251]
    DIRECTION INPUT ;
    USE SIGNAL ;
    SHAPE ABUTMENT ;
    PORT
      LAYER M4 ;
      RECT 0.000 75.888 0.024 75.912 ;
    END
  END wd_in[251]
  PIN wd_in[252]
    DIRECTION INPUT ;
    USE SIGNAL ;
    SHAPE ABUTMENT ;
    PORT
      LAYER M4 ;
      RECT 0.000 76.032 0.024 76.056 ;
    END
  END wd_in[252]
  PIN wd_in[253]
    DIRECTION INPUT ;
    USE SIGNAL ;
    SHAPE ABUTMENT ;
    PORT
      LAYER M4 ;
      RECT 0.000 76.176 0.024 76.200 ;
    END
  END wd_in[253]
  PIN wd_in[254]
    DIRECTION INPUT ;
    USE SIGNAL ;
    SHAPE ABUTMENT ;
    PORT
      LAYER M4 ;
      RECT 0.000 76.320 0.024 76.344 ;
    END
  END wd_in[254]
  PIN wd_in[255]
    DIRECTION INPUT ;
    USE SIGNAL ;
    SHAPE ABUTMENT ;
    PORT
      LAYER M4 ;
      RECT 0.000 76.464 0.024 76.488 ;
    END
  END wd_in[255]
  PIN addr_in[0]
    DIRECTION INPUT ;
    USE SIGNAL ;
    SHAPE ABUTMENT ;
    PORT
      LAYER M4 ;
      RECT 0.000 79.440 0.024 79.464 ;
    END
  END addr_in[0]
  PIN addr_in[1]
    DIRECTION INPUT ;
    USE SIGNAL ;
    SHAPE ABUTMENT ;
    PORT
      LAYER M4 ;
      RECT 0.000 79.584 0.024 79.608 ;
    END
  END addr_in[1]
  PIN addr_in[2]
    DIRECTION INPUT ;
    USE SIGNAL ;
    SHAPE ABUTMENT ;
    PORT
      LAYER M4 ;
      RECT 0.000 79.728 0.024 79.752 ;
    END
  END addr_in[2]
  PIN addr_in[3]
    DIRECTION INPUT ;
    USE SIGNAL ;
    SHAPE ABUTMENT ;
    PORT
      LAYER M4 ;
      RECT 0.000 79.872 0.024 79.896 ;
    END
  END addr_in[3]
  PIN addr_in[4]
    DIRECTION INPUT ;
    USE SIGNAL ;
    SHAPE ABUTMENT ;
    PORT
      LAYER M4 ;
      RECT 0.000 80.016 0.024 80.040 ;
    END
  END addr_in[4]
  PIN addr_in[5]
    DIRECTION INPUT ;
    USE SIGNAL ;
    SHAPE ABUTMENT ;
    PORT
      LAYER M4 ;
      RECT 0.000 80.160 0.024 80.184 ;
    END
  END addr_in[5]
  PIN addr_in[6]
    DIRECTION INPUT ;
    USE SIGNAL ;
    SHAPE ABUTMENT ;
    PORT
      LAYER M4 ;
      RECT 0.000 80.304 0.024 80.328 ;
    END
  END addr_in[6]
  PIN addr_in[7]
    DIRECTION INPUT ;
    USE SIGNAL ;
    SHAPE ABUTMENT ;
    PORT
      LAYER M4 ;
      RECT 0.000 80.448 0.024 80.472 ;
    END
  END addr_in[7]
  PIN we_in
    DIRECTION INPUT ;
    USE SIGNAL ;
    SHAPE ABUTMENT ;
    PORT
      LAYER M4 ;
      RECT 0.000 83.424 0.024 83.448 ;
    END
  END we_in
  PIN ce_in
    DIRECTION INPUT ;
    USE SIGNAL ;
    SHAPE ABUTMENT ;
    PORT
      LAYER M4 ;
      RECT 0.000 83.568 0.024 83.592 ;
    END
  END ce_in
  PIN clk
    DIRECTION INPUT ;
    USE SIGNAL ;
    SHAPE ABUTMENT ;
    PORT
      LAYER M4 ;
      RECT 0.000 83.712 0.024 83.736 ;
    END
  END clk
  PIN VSS
    DIRECTION INOUT ;
    USE GROUND ;
    PORT
      LAYER M4 ;
      RECT 0.048 0.000 33.202 0.096 ;
      RECT 0.048 0.768 33.202 0.864 ;
      RECT 0.048 1.536 33.202 1.632 ;
      RECT 0.048 2.304 33.202 2.400 ;
      RECT 0.048 3.072 33.202 3.168 ;
      RECT 0.048 3.840 33.202 3.936 ;
      RECT 0.048 4.608 33.202 4.704 ;
      RECT 0.048 5.376 33.202 5.472 ;
      RECT 0.048 6.144 33.202 6.240 ;
      RECT 0.048 6.912 33.202 7.008 ;
      RECT 0.048 7.680 33.202 7.776 ;
      RECT 0.048 8.448 33.202 8.544 ;
      RECT 0.048 9.216 33.202 9.312 ;
      RECT 0.048 9.984 33.202 10.080 ;
      RECT 0.048 10.752 33.202 10.848 ;
      RECT 0.048 11.520 33.202 11.616 ;
      RECT 0.048 12.288 33.202 12.384 ;
      RECT 0.048 13.056 33.202 13.152 ;
      RECT 0.048 13.824 33.202 13.920 ;
      RECT 0.048 14.592 33.202 14.688 ;
      RECT 0.048 15.360 33.202 15.456 ;
      RECT 0.048 16.128 33.202 16.224 ;
      RECT 0.048 16.896 33.202 16.992 ;
      RECT 0.048 17.664 33.202 17.760 ;
      RECT 0.048 18.432 33.202 18.528 ;
      RECT 0.048 19.200 33.202 19.296 ;
      RECT 0.048 19.968 33.202 20.064 ;
      RECT 0.048 20.736 33.202 20.832 ;
      RECT 0.048 21.504 33.202 21.600 ;
      RECT 0.048 22.272 33.202 22.368 ;
      RECT 0.048 23.040 33.202 23.136 ;
      RECT 0.048 23.808 33.202 23.904 ;
      RECT 0.048 24.576 33.202 24.672 ;
      RECT 0.048 25.344 33.202 25.440 ;
      RECT 0.048 26.112 33.202 26.208 ;
      RECT 0.048 26.880 33.202 26.976 ;
      RECT 0.048 27.648 33.202 27.744 ;
      RECT 0.048 28.416 33.202 28.512 ;
      RECT 0.048 29.184 33.202 29.280 ;
      RECT 0.048 29.952 33.202 30.048 ;
      RECT 0.048 30.720 33.202 30.816 ;
      RECT 0.048 31.488 33.202 31.584 ;
      RECT 0.048 32.256 33.202 32.352 ;
      RECT 0.048 33.024 33.202 33.120 ;
      RECT 0.048 33.792 33.202 33.888 ;
      RECT 0.048 34.560 33.202 34.656 ;
      RECT 0.048 35.328 33.202 35.424 ;
      RECT 0.048 36.096 33.202 36.192 ;
      RECT 0.048 36.864 33.202 36.960 ;
      RECT 0.048 37.632 33.202 37.728 ;
      RECT 0.048 38.400 33.202 38.496 ;
      RECT 0.048 39.168 33.202 39.264 ;
      RECT 0.048 39.936 33.202 40.032 ;
      RECT 0.048 40.704 33.202 40.800 ;
      RECT 0.048 41.472 33.202 41.568 ;
      RECT 0.048 42.240 33.202 42.336 ;
      RECT 0.048 43.008 33.202 43.104 ;
      RECT 0.048 43.776 33.202 43.872 ;
      RECT 0.048 44.544 33.202 44.640 ;
      RECT 0.048 45.312 33.202 45.408 ;
      RECT 0.048 46.080 33.202 46.176 ;
      RECT 0.048 46.848 33.202 46.944 ;
      RECT 0.048 47.616 33.202 47.712 ;
      RECT 0.048 48.384 33.202 48.480 ;
      RECT 0.048 49.152 33.202 49.248 ;
      RECT 0.048 49.920 33.202 50.016 ;
      RECT 0.048 50.688 33.202 50.784 ;
      RECT 0.048 51.456 33.202 51.552 ;
      RECT 0.048 52.224 33.202 52.320 ;
      RECT 0.048 52.992 33.202 53.088 ;
      RECT 0.048 53.760 33.202 53.856 ;
      RECT 0.048 54.528 33.202 54.624 ;
      RECT 0.048 55.296 33.202 55.392 ;
      RECT 0.048 56.064 33.202 56.160 ;
      RECT 0.048 56.832 33.202 56.928 ;
      RECT 0.048 57.600 33.202 57.696 ;
      RECT 0.048 58.368 33.202 58.464 ;
      RECT 0.048 59.136 33.202 59.232 ;
      RECT 0.048 59.904 33.202 60.000 ;
      RECT 0.048 60.672 33.202 60.768 ;
      RECT 0.048 61.440 33.202 61.536 ;
      RECT 0.048 62.208 33.202 62.304 ;
      RECT 0.048 62.976 33.202 63.072 ;
      RECT 0.048 63.744 33.202 63.840 ;
      RECT 0.048 64.512 33.202 64.608 ;
      RECT 0.048 65.280 33.202 65.376 ;
      RECT 0.048 66.048 33.202 66.144 ;
      RECT 0.048 66.816 33.202 66.912 ;
      RECT 0.048 67.584 33.202 67.680 ;
      RECT 0.048 68.352 33.202 68.448 ;
      RECT 0.048 69.120 33.202 69.216 ;
      RECT 0.048 69.888 33.202 69.984 ;
      RECT 0.048 70.656 33.202 70.752 ;
      RECT 0.048 71.424 33.202 71.520 ;
      RECT 0.048 72.192 33.202 72.288 ;
      RECT 0.048 72.960 33.202 73.056 ;
      RECT 0.048 73.728 33.202 73.824 ;
      RECT 0.048 74.496 33.202 74.592 ;
      RECT 0.048 75.264 33.202 75.360 ;
      RECT 0.048 76.032 33.202 76.128 ;
      RECT 0.048 76.800 33.202 76.896 ;
      RECT 0.048 77.568 33.202 77.664 ;
      RECT 0.048 78.336 33.202 78.432 ;
      RECT 0.048 79.104 33.202 79.200 ;
      RECT 0.048 79.872 33.202 79.968 ;
      RECT 0.048 80.640 33.202 80.736 ;
      RECT 0.048 81.408 33.202 81.504 ;
      RECT 0.048 82.176 33.202 82.272 ;
      RECT 0.048 82.944 33.202 83.040 ;
      RECT 0.048 83.712 33.202 83.808 ;
    END
  END VSS
  PIN VDD
    DIRECTION INOUT ;
    USE POWER ;
    PORT
      LAYER M4 ;
      RECT 0.048 0.384 33.202 0.480 ;
      RECT 0.048 1.152 33.202 1.248 ;
      RECT 0.048 1.920 33.202 2.016 ;
      RECT 0.048 2.688 33.202 2.784 ;
      RECT 0.048 3.456 33.202 3.552 ;
      RECT 0.048 4.224 33.202 4.320 ;
      RECT 0.048 4.992 33.202 5.088 ;
      RECT 0.048 5.760 33.202 5.856 ;
      RECT 0.048 6.528 33.202 6.624 ;
      RECT 0.048 7.296 33.202 7.392 ;
      RECT 0.048 8.064 33.202 8.160 ;
      RECT 0.048 8.832 33.202 8.928 ;
      RECT 0.048 9.600 33.202 9.696 ;
      RECT 0.048 10.368 33.202 10.464 ;
      RECT 0.048 11.136 33.202 11.232 ;
      RECT 0.048 11.904 33.202 12.000 ;
      RECT 0.048 12.672 33.202 12.768 ;
      RECT 0.048 13.440 33.202 13.536 ;
      RECT 0.048 14.208 33.202 14.304 ;
      RECT 0.048 14.976 33.202 15.072 ;
      RECT 0.048 15.744 33.202 15.840 ;
      RECT 0.048 16.512 33.202 16.608 ;
      RECT 0.048 17.280 33.202 17.376 ;
      RECT 0.048 18.048 33.202 18.144 ;
      RECT 0.048 18.816 33.202 18.912 ;
      RECT 0.048 19.584 33.202 19.680 ;
      RECT 0.048 20.352 33.202 20.448 ;
      RECT 0.048 21.120 33.202 21.216 ;
      RECT 0.048 21.888 33.202 21.984 ;
      RECT 0.048 22.656 33.202 22.752 ;
      RECT 0.048 23.424 33.202 23.520 ;
      RECT 0.048 24.192 33.202 24.288 ;
      RECT 0.048 24.960 33.202 25.056 ;
      RECT 0.048 25.728 33.202 25.824 ;
      RECT 0.048 26.496 33.202 26.592 ;
      RECT 0.048 27.264 33.202 27.360 ;
      RECT 0.048 28.032 33.202 28.128 ;
      RECT 0.048 28.800 33.202 28.896 ;
      RECT 0.048 29.568 33.202 29.664 ;
      RECT 0.048 30.336 33.202 30.432 ;
      RECT 0.048 31.104 33.202 31.200 ;
      RECT 0.048 31.872 33.202 31.968 ;
      RECT 0.048 32.640 33.202 32.736 ;
      RECT 0.048 33.408 33.202 33.504 ;
      RECT 0.048 34.176 33.202 34.272 ;
      RECT 0.048 34.944 33.202 35.040 ;
      RECT 0.048 35.712 33.202 35.808 ;
      RECT 0.048 36.480 33.202 36.576 ;
      RECT 0.048 37.248 33.202 37.344 ;
      RECT 0.048 38.016 33.202 38.112 ;
      RECT 0.048 38.784 33.202 38.880 ;
      RECT 0.048 39.552 33.202 39.648 ;
      RECT 0.048 40.320 33.202 40.416 ;
      RECT 0.048 41.088 33.202 41.184 ;
      RECT 0.048 41.856 33.202 41.952 ;
      RECT 0.048 42.624 33.202 42.720 ;
      RECT 0.048 43.392 33.202 43.488 ;
      RECT 0.048 44.160 33.202 44.256 ;
      RECT 0.048 44.928 33.202 45.024 ;
      RECT 0.048 45.696 33.202 45.792 ;
      RECT 0.048 46.464 33.202 46.560 ;
      RECT 0.048 47.232 33.202 47.328 ;
      RECT 0.048 48.000 33.202 48.096 ;
      RECT 0.048 48.768 33.202 48.864 ;
      RECT 0.048 49.536 33.202 49.632 ;
      RECT 0.048 50.304 33.202 50.400 ;
      RECT 0.048 51.072 33.202 51.168 ;
      RECT 0.048 51.840 33.202 51.936 ;
      RECT 0.048 52.608 33.202 52.704 ;
      RECT 0.048 53.376 33.202 53.472 ;
      RECT 0.048 54.144 33.202 54.240 ;
      RECT 0.048 54.912 33.202 55.008 ;
      RECT 0.048 55.680 33.202 55.776 ;
      RECT 0.048 56.448 33.202 56.544 ;
      RECT 0.048 57.216 33.202 57.312 ;
      RECT 0.048 57.984 33.202 58.080 ;
      RECT 0.048 58.752 33.202 58.848 ;
      RECT 0.048 59.520 33.202 59.616 ;
      RECT 0.048 60.288 33.202 60.384 ;
      RECT 0.048 61.056 33.202 61.152 ;
      RECT 0.048 61.824 33.202 61.920 ;
      RECT 0.048 62.592 33.202 62.688 ;
      RECT 0.048 63.360 33.202 63.456 ;
      RECT 0.048 64.128 33.202 64.224 ;
      RECT 0.048 64.896 33.202 64.992 ;
      RECT 0.048 65.664 33.202 65.760 ;
      RECT 0.048 66.432 33.202 66.528 ;
      RECT 0.048 67.200 33.202 67.296 ;
      RECT 0.048 67.968 33.202 68.064 ;
      RECT 0.048 68.736 33.202 68.832 ;
      RECT 0.048 69.504 33.202 69.600 ;
      RECT 0.048 70.272 33.202 70.368 ;
      RECT 0.048 71.040 33.202 71.136 ;
      RECT 0.048 71.808 33.202 71.904 ;
      RECT 0.048 72.576 33.202 72.672 ;
      RECT 0.048 73.344 33.202 73.440 ;
      RECT 0.048 74.112 33.202 74.208 ;
      RECT 0.048 74.880 33.202 74.976 ;
      RECT 0.048 75.648 33.202 75.744 ;
      RECT 0.048 76.416 33.202 76.512 ;
      RECT 0.048 77.184 33.202 77.280 ;
      RECT 0.048 77.952 33.202 78.048 ;
      RECT 0.048 78.720 33.202 78.816 ;
      RECT 0.048 79.488 33.202 79.584 ;
      RECT 0.048 80.256 33.202 80.352 ;
      RECT 0.048 81.024 33.202 81.120 ;
      RECT 0.048 81.792 33.202 81.888 ;
      RECT 0.048 82.560 33.202 82.656 ;
      RECT 0.048 83.328 33.202 83.424 ;
    END
  END VDD
  OBS
    LAYER M1 ;
    RECT 0 0 33.250 84.000 ;
    LAYER M2 ;
    RECT 0 0 33.250 84.000 ;
    LAYER M3 ;
    RECT 0 0 33.250 84.000 ;
    LAYER M4 ;
    RECT 0 0 33.250 84.000 ;
  END
END fakeram7_256x256

END LIBRARY
